              <bitWidth>1</bitWidth>
              <access>read-only</access>
              <enumeratedValues>
                <enumeratedValue>
                  <name>0</name>
                  <description>Module 6 input was not a wakeup source</description>
                  <value>#0</value>
                </enumeratedValue>
                <enumeratedValue>
                  <name>1</name>
                  <description>Module 6 input was a wakeup source</description>
                  <value>#1</value>
                </enumeratedValue>
              </enumeratedValues>
            </field>
            <field>
              <name>MWUF7</name>
              <description>Wakeup flag For module 7</description>
              <bitOffset>7</bitOffset>
              <bitWidth>1</bitWidth>
              <access>read-only</access>
              <enumeratedValues>
                <enumeratedValue>
                  <name>0</name>
                  <description>Module 7 input was not a wakeup source</description>
                  <value>#0</value>
                </enumeratedValue>
                <enumeratedValue>
                  <name>1</name>
                  <description>Module 7 input was a wakeup source</description>
                  <value>#1</value>
                </enumeratedValue>
              </enumeratedValues>
            </field>
          </fields>
        </register>
        <register>
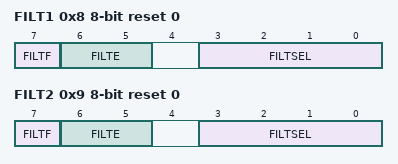
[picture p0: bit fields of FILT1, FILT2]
          <name>FILT1</name>
          <description>LLWU Pin Filter 1 register</description>
          <addressOffset>0x8</addressOffset>
          <size>8</size>
          <access>read-write</access>
          <resetValue>0</resetValue>
          <resetMask>0xFF</resetMask>
          <fields>
            <field>
              <name>FILTSEL</name>
              <description>Filter Pin Select</description>
              <bitOffset>0</bitOffset>
              <bitWidth>4</bitWidth>
              <access>read-write</access>
              <enumeratedValues>
                <enumeratedValue>
                  <name>0000</name>
                  <description>Select LLWU_P0 for filter</description>
                  <value>#0000</value>
                </enumeratedValue>
                <enumeratedValue>
                  <name>1111</name>
                  <description>Select LLWU_P15 for filter</description>
                  <value>#1111</value>
                </enumeratedValue>
              </enumeratedValues>
            </field>
            <field>
              <name>FILTE</name>
              <description>Digital Filter On External Pin</description>
              <bitOffset>5</bitOffset>
              <bitWidth>2</bitWidth>
              <access>read-write</access>
              <enumeratedValues>
                <enumeratedValue>
                  <name>00</name>
                  <description>Filter disabled</description>
                  <value>#00</value>
                </enumeratedValue>
                <enumeratedValue>
                  <name>01</name>
                  <description>Filter posedge detect enabled</description>
                  <value>#01</value>
                </enumeratedValue>
                <enumeratedValue>
                  <name>10</name>
                  <description>Filter negedge detect enabled</description>
                  <value>#10</value>
                </enumeratedValue>
                <enumeratedValue>
                  <name>11</name>
                  <description>Filter any edge detect enabled</description>
                  <value>#11</value>
                </enumeratedValue>
              </enumeratedValues>
            </field>
            <field>
              <name>FILTF</name>
              <description>Filter Detect Flag</description>
              <bitOffset>7</bitOffset>
              <bitWidth>1</bitWidth>
              <access>read-write</access>
              <enumeratedValues>
                <enumeratedValue>
                  <name>0</name>
                  <description>Pin Filter 1 was not a wakeup source</description>
                  <value>#0</value>
                </enumeratedValue>
                <enumeratedValue>
                  <name>1</name>
                  <description>Pin Filter 1 was a wakeup source</description>
                  <value>#1</value>
                </enumeratedValue>
              </enumeratedValues>
            </field>
          </fields>
        </register>
        <register>
          <name>FILT2</name>
          <description>LLWU Pin Filter 2 register</description>
          <addressOffset>0x9</addressOffset>
          <size>8</size>
          <access>read-write</access>
          <resetValue>0</resetValue>
          <resetMask>0xFF</resetMask>
          <fields>
            <field>
              <name>FILTSEL</name>
              <description>Filter Pin Select</description>
              <bitOffset>0</bitOffset>
              <bitWidth>4</bitWidth>
              <access>read-write</access>
              <enumeratedValues>
                <enumeratedValue>
                  <name>0000</name>
                  <description>Select LLWU_P0 for filter</description>
                  <value>#0000</value>
                </enumeratedValue>
                <enumeratedValue>
                  <name>1111</name>
                  <description>Select LLWU_P15 for filter</description>
                  <value>#1111</value>
                </enumeratedValue>
              </enumeratedValues>
            </field>
            <field>
              <name>FILTE</name>
              <description>Digital Filter On External Pin</description>
              <bitOffset>5</bitOffset>
              <bitWidth>2</bitWidth>
              <access>read-write</access>
              <enumeratedValues>
                <enumeratedValue>
                  <name>00</name>
                  <description>Filter disabled</description>
                  <value>#00</value>
                </enumeratedValue>
                <enumeratedValue>
                  <name>01</name>
                  <description>Filter posedge detect enabled</description>
                  <value>#01</value>
                </enumeratedValue>
                <enumeratedValue>
                  <name>10</name>
                  <description>Filter negedge detect enabled</description>
                  <value>#10</value>
                </enumeratedValue>
                <enumeratedValue>
                  <name>11</name>
                  <description>Filter any edge detect enabled</description>
                  <value>#11</value>
                </enumeratedValue>
              </enumeratedValues>
            </field>
            <field>
              <name>FILTF</name>
              <description>Filter Detect Flag</description>
              <bitOffset>7</bitOffset>
              <bitWidth>1</bitWidth>
              <access>read-write</access>
              <enumeratedValues>
                <enumeratedValue>
                  <name>0</name>
                  <description>Pin Filter 2 was not a wakeup source</description>
                  <value>#0</value>
                </enumeratedValue>
                <enumeratedValue>
                  <name>1</name>
                  <description>Pin Filter 2 was a wakeup source</description>
                  <value>#1</value>
                </enumeratedValue>
              </enumeratedValues>
            </field>
          </fields>
        </register>
      </registers>
    </peripheral>
    <peripheral>
      <name>PMC</name>
      <description>Power Management Controller</description>
      <prependToName>PMC_</prependToName>
      <baseAddress>0x4007D000</baseAddress>
      <addressBlock>
        <offset>0</offset>
        <size>0x3</size>
        <usage>registers</usage>
      </addressBlock>
      <interrupt>
        <name>LVD_LVW</name>
        <value>6</value>
      </interrupt>
      <registers>
        <register>
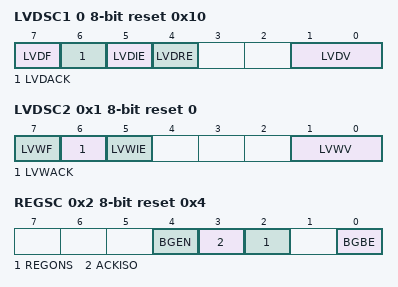
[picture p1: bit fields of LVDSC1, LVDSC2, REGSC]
          <name>LVDSC1</name>
          <description>Low Voltage Detect Status And Control 1 register</description>
          <addressOffset>0</addressOffset>
          <size>8</size>
          <access>read-write</access>
          <resetValue>0x10</resetValue>
          <resetMask>0xFF</resetMask>
          <fields>
            <field>
              <name>LVDV</name>
              <description>Low-Voltage Detect Voltage Select</description>
              <bitOffset>0</bitOffset>
              <bitWidth>2</bitWidth>
              <access>read-write</access>
              <enumeratedValues>
                <enumeratedValue>
                  <name>00</name>
                  <description>Low trip point selected (V LVD = V LVDL )</description>
                  <value>#00</value>
                </enumeratedValue>
                <enumeratedValue>
                  <name>01</name>
                  <description>High trip point selected (V LVD = V LVDH )</description>
                  <value>#01</value>
                </enumeratedValue>
              </enumeratedValues>
            </field>
            <field>
              <name>LVDRE</name>
              <description>Low-Voltage Detect Reset Enable</description>
              <bitOffset>4</bitOffset>
              <bitWidth>1</bitWidth>
              <access>read-write</access>
              <enumeratedValues>
                <enumeratedValue>
                  <name>0</name>
                  <description>LVDF does not generate hardware resets</description>
                  <value>#0</value>
                </enumeratedValue>
                <enumeratedValue>
                  <name>1</name>
                  <description>Force an MCU reset when LVDF = 1</description>
                  <value>#1</value>
                </enumeratedValue>
              </enumeratedValues>
            </field>
            <field>
              <name>LVDIE</name>
              <description>Low-Voltage Detect Interrupt Enable</description>
              <bitOffset>5</bitOffset>
              <bitWidth>1</bitWidth>
              <access>read-write</access>
              <enumeratedValues>
                <enumeratedValue>
                  <name>0</name>
                  <description>Hardware interrupt disabled (use polling)</description>
                  <value>#0</value>
                </enumeratedValue>
                <enumeratedValue>
                  <name>1</name>
                  <description>Request a hardware interrupt when LVDF = 1</description>
                  <value>#1</value>
                </enumeratedValue>
              </enumeratedValues>
            </field>
            <field>
              <name>LVDACK</name>
              <description>Low-Voltage Detect Acknowledge</description>
              <bitOffset>6</bitOffset>
              <bitWidth>1</bitWidth>
              <access>write-only</access>
            </field>
            <field>
              <name>LVDF</name>
              <description>Low-Voltage Detect Flag</description>
              <bitOffset>7</bitOffset>
              <bitWidth>1</bitWidth>
              <access>read-only</access>
              <enumeratedValues>
                <enumeratedValue>
                  <name>0</name>
                  <description>Low-voltage event not detected</description>
                  <value>#0</value>
                </enumeratedValue>
                <enumeratedValue>
                  <name>1</name>
                  <description>Low-voltage event detected</description>
                  <value>#1</value>
                </enumeratedValue>
              </enumeratedValues>
            </field>
          </fields>
        </register>
        <register>
          <name>LVDSC2</name>
          <description>Low Voltage Detect Status And Control 2 register</description>
          <addressOffset>0x1</addressOffset>
          <size>8</size>
          <access>read-write</access>
          <resetValue>0</resetValue>
          <resetMask>0xFF</resetMask>
          <fields>
            <field>
              <name>LVWV</name>
              <description>Low-Voltage Warning Voltage Select</description>
              <bitOffset>0</bitOffset>
              <bitWidth>2</bitWidth>
              <access>read-write</access>
              <enumeratedValues>
                <enumeratedValue>
                  <name>00</name>
                  <description>Low trip point selected (VLVW = VLVW1)</description>
                  <value>#00</value>
                </enumeratedValue>
                <enumeratedValue>
                  <name>01</name>
                  <description>Mid 1 trip point selected (VLVW = VLVW2)</description>
                  <value>#01</value>
                </enumeratedValue>
                <enumeratedValue>
                  <name>10</name>
                  <description>Mid 2 trip point selected (VLVW = VLVW3)</description>
                  <value>#10</value>
                </enumeratedValue>
                <enumeratedValue>
                  <name>11</name>
                  <description>High trip point selected (VLVW = VLVW4)</description>
                  <value>#11</value>
                </enumeratedValue>
              </enumeratedValues>
            </field>
            <field>
              <name>LVWIE</name>
              <description>Low-Voltage Warning Interrupt Enable</description>
              <bitOffset>5</bitOffset>
              <bitWidth>1</bitWidth>
              <access>read-write</access>
              <enumeratedValues>
                <enumeratedValue>
                  <name>0</name>
                  <description>Hardware interrupt disabled (use polling)</description>
                  <value>#0</value>
                </enumeratedValue>
                <enumeratedValue>
                  <name>1</name>
                  <description>Request a hardware interrupt when LVWF = 1</description>
                  <value>#1</value>
                </enumeratedValue>
              </enumeratedValues>
            </field>
            <field>
              <name>LVWACK</name>
              <description>Low-Voltage Warning Acknowledge</description>
              <bitOffset>6</bitOffset>
              <bitWidth>1</bitWidth>
              <access>write-only</access>
            </field>
            <field>
              <name>LVWF</name>
              <description>Low-Voltage Warning Flag</description>
              <bitOffset>7</bitOffset>
              <bitWidth>1</bitWidth>
              <access>read-only</access>
              <enumeratedValues>
                <enumeratedValue>
                  <name>0</name>
                  <description>Low-voltage warning event not detected</description>
                  <value>#0</value>
                </enumeratedValue>
                <enumeratedValue>
                  <name>1</name>
                  <description>Low-voltage warning event detected</description>
                  <value>#1</value>
                </enumeratedValue>
              </enumeratedValues>
            </field>
          </fields>
        </register>
        <register>
          <name>REGSC</name>
          <description>Regulator Status And Control register</description>
          <addressOffset>0x2</addressOffset>
          <size>8</size>
          <access>read-write</access>
          <resetValue>0x4</resetValue>
          <resetMask>0xFF</resetMask>
          <fields>
            <field>
              <name>BGBE</name>
              <description>Bandgap Buffer Enable</description>
              <bitOffset>0</bitOffset>
              <bitWidth>1</bitWidth>
              <access>read-write</access>
              <enumeratedValues>
                <enumeratedValue>
                  <name>0</name>
                  <description>Bandgap buffer not enabled</description>
                  <value>#0</value>
                </enumeratedValue>
                <enumeratedValue>
                  <name>1</name>
                  <description>Bandgap buffer enabled</description>
                  <value>#1</value>
                </enumeratedValue>
              </enumeratedValues>
            </field>
            <field>
              <name>REGONS</name>
              <description>Regulator In Run Regulation Status</description>
              <bitOffset>2</bitOffset>
              <bitWidth>1</bitWidth>
              <access>read-only</access>
              <enumeratedValues>
                <enumeratedValue>
                  <name>0</name>
                  <description>Regulator is in stop regulation or in transition to/from it</description>
                  <value>#0</value>
                </enumeratedValue>
                <enumeratedValue>
                  <name>1</name>
                  <description>Regulator is in run regulation</description>
                  <value>#1</value>
                </enumeratedValue>
              </enumeratedValues>
            </field>
            <field>
              <name>ACKISO</name>
              <description>Acknowledge Isolation</description>
              <bitOffset>3</bitOffset>
              <bitWidth>1</bitWidth>
              <access>read-write</access>
              <enumeratedValues>
                <enumeratedValue>
                  <name>0</name>
                  <description>Peripherals and I/O pads are in normal run state.</description>
                  <value>#0</value>
                </enumeratedValue>
                <enumeratedValue>
                  <name>1</name>
                  <description>Certain peripherals and I/O pads are in an isolated and latched state.</description>
                  <value>#1</value>
                </enumeratedValue>
              </enumeratedValues>
            </field>
            <field>
              <name>BGEN</name>
              <description>Bandgap Enable In VLPx Operation</description>
              <bitOffset>4</bitOffset>
              <bitWidth>1</bitWidth>
              <access>read-write</access>
              <enumeratedValues>
                <enumeratedValue>
                  <name>0</name>
                  <description>Bandgap voltage reference is disabled in VLPx , LLS , and VLLSx modes.</description>
                  <value>#0</value>
                </enumeratedValue>
                <enumeratedValue>
                  <name>1</name>
                  <description>Bandgap voltage reference is enabled in VLPx , LLS , and VLLSx modes.</description>
                  <value>#1</value>
                </enumeratedValue>
              </enumeratedValues>
            </field>
          </fields>
        </register>
      </registers>
    </peripheral>
    <peripheral>
      <name>SMC</name>
      <description>System Mode Controller</description>
      <prependToName>SMC_</prependToName>
      <baseAddress>0x4007E000</baseAddress>
      <addressBlock>
        <offset>0</offset>
        <size>0x4</size>
        <usage>registers</usage>
      </addressBlock>
      <registers>
        <register>
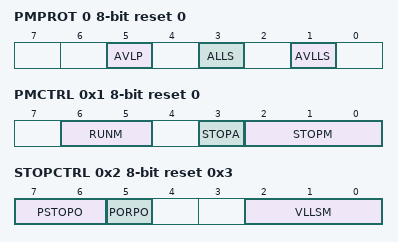
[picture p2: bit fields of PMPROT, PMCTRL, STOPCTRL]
          <name>PMPROT</name>
          <description>Power Mode Protection register</description>
          <addressOffset>0</addressOffset>
          <size>8</size>
          <access>read-write</access>
          <resetValue>0</resetValue>
          <resetMask>0xFF</resetMask>
          <fields>
            <field>
              <name>AVLLS</name>
              <description>Allow Very-Low-Leakage Stop Mode</description>
              <bitOffset>1</bitOffset>
              <bitWidth>1</bitWidth>
              <access>read-write</access>
              <enumeratedValues>
                <enumeratedValue>
                  <name>0</name>
                  <description>Any VLLSx mode is not allowed</description>
                  <value>#0</value>
                </enumeratedValue>
                <enumeratedValue>
                  <name>1</name>
                  <description>Any VLLSx mode is allowed</description>
                  <value>#1</value>
                </enumeratedValue>
              </enumeratedValues>
            </field>
            <field>
              <name>ALLS</name>
              <description>Allow Low-Leakage Stop Mode</description>
              <bitOffset>3</bitOffset>
              <bitWidth>1</bitWidth>
              <access>read-write</access>
              <enumeratedValues>
                <enumeratedValue>
                  <name>0</name>
                  <description>LLS is not allowed</description>
                  <value>#0</value>
                </enumeratedValue>
                <enumeratedValue>
                  <name>1</name>
                  <description>LLS is allowed</description>
                  <value>#1</value>
                </enumeratedValue>
              </enumeratedValues>
            </field>
            <field>
              <name>AVLP</name>
              <description>Allow Very-Low-Power Modes</description>
              <bitOffset>5</bitOffset>
              <bitWidth>1</bitWidth>
              <access>read-write</access>
              <enumeratedValues>
                <enumeratedValue>
                  <name>0</name>
                  <description>VLPR, VLPW, and VLPS are not allowed.</description>
                  <value>#0</value>
                </enumeratedValue>
                <enumeratedValue>
                  <name>1</name>
                  <description>VLPR, VLPW, and VLPS are allowed.</description>
                  <value>#1</value>
                </enumeratedValue>
              </enumeratedValues>
            </field>
          </fields>
        </register>
        <register>
          <name>PMCTRL</name>
          <description>Power Mode Control register</description>
          <addressOffset>0x1</addressOffset>
          <size>8</size>
          <access>read-write</access>
          <resetValue>0</resetValue>
          <resetMask>0xFF</resetMask>
          <fields>
            <field>
              <name>STOPM</name>
              <description>Stop Mode Control</description>
              <bitOffset>0</bitOffset>
              <bitWidth>3</bitWidth>
              <access>read-write</access>
              <enumeratedValues>
                <enumeratedValue>
                  <name>000</name>
                  <description>Normal Stop (STOP)</description>
                  <value>#000</value>
                </enumeratedValue>
                <enumeratedValue>
                  <name>010</name>
                  <description>Very-Low-Power Stop (VLPS)</description>
                  <value>#010</value>
                </enumeratedValue>
                <enumeratedValue>
                  <name>011</name>
                  <description>Low-Leakage Stop (LLS)</description>
                  <value>#011</value>
                </enumeratedValue>
                <enumeratedValue>
                  <name>100</name>
                  <description>Very-Low-Leakage Stop (VLLSx)</description>
                  <value>#100</value>
                </enumeratedValue>
                <enumeratedValue>
                  <name>110</name>
                  <description>Reseved</description>
                  <value>#110</value>
                </enumeratedValue>
              </enumeratedValues>
            </field>
            <field>
              <name>STOPA</name>
              <description>Stop Aborted</description>
              <bitOffset>3</bitOffset>
              <bitWidth>1</bitWidth>
              <access>read-only</access>
              <enumeratedValues>
                <enumeratedValue>
                  <name>0</name>
                  <description>The previous stop mode entry was successsful.</description>
                  <value>#0</value>
                </enumeratedValue>
                <enumeratedValue>
                  <name>1</name>
                  <description>The previous stop mode entry was aborted.</description>
                  <value>#1</value>
                </enumeratedValue>
              </enumeratedValues>
            </field>
            <field>
              <name>RUNM</name>
              <description>Run Mode Control</description>
              <bitOffset>5</bitOffset>
              <bitWidth>2</bitWidth>
              <access>read-write</access>
              <enumeratedValues>
                <enumeratedValue>
                  <name>00</name>
                  <description>Normal Run mode (RUN)</description>
                  <value>#00</value>
                </enumeratedValue>
                <enumeratedValue>
                  <name>10</name>
                  <description>Very-Low-Power Run mode (VLPR)</description>
                  <value>#10</value>
                </enumeratedValue>
              </enumeratedValues>
            </field>
          </fields>
        </register>
        <register>
          <name>STOPCTRL</name>
          <description>Stop Control Register</description>
          <addressOffset>0x2</addressOffset>
          <size>8</size>
          <access>read-write</access>
          <resetValue>0x3</resetValue>
          <resetMask>0xFF</resetMask>
          <fields>
            <field>
              <name>VLLSM</name>
              <description>VLLS Mode Control</description>
              <bitOffset>0</bitOffset>
              <bitWidth>3</bitWidth>
              <access>read-write</access>
              <enumeratedValues>
                <enumeratedValue>
                  <name>000</name>
                  <description>VLLS0</description>
                  <value>#000</value>
                </enumeratedValue>
                <enumeratedValue>
                  <name>001</name>
                  <description>VLLS1</description>
                  <value>#001</value>
                </enumeratedValue>
                <enumeratedValue>
                  <name>011</name>
                  <description>VLLS3</description>
                  <value>#011</value>
                </enumeratedValue>
              </enumeratedValues>
            </field>
            <field>
              <name>PORPO</name>
              <description>POR Power Option</description>
              <bitOffset>5</bitOffset>
              <bitWidth>1</bitWidth>
              <access>read-write</access>
              <enumeratedValues>
                <enumeratedValue>
                  <name>0</name>
                  <description>POR detect circuit is enabled in VLLS0</description>
                  <value>#0</value>
                </enumeratedValue>
                <enumeratedValue>
                  <name>1</name>
                  <description>POR detect circuit is disabled in VLLS0</description>
                  <value>#1</value>
                </enumeratedValue>
              </enumeratedValues>
            </field>
            <field>
              <name>PSTOPO</name>
              <description>Partial Stop Option</description>
              <bitOffset>6</bitOffset>
              <bitWidth>2</bitWidth>
              <access>read-write</access>
              <enumeratedValues>
                <enumeratedValue>
                  <name>00</name>
                  <description>STOP - Normal Stop mode</description>
                  <value>#00</value>
                </enumeratedValue>
                <enumeratedValue>
                  <name>01</name>
                  <description>PSTOP1 - Partial Stop with both system and bus clocks disabled</description>
                  <value>#01</value>
                </enumeratedValue>
                <enumeratedValue>
                  <name>10</name>
                  <description>PSTOP2 - Partial Stop with system clock disabled and bus clock enabled</description>
                  <value>#10</value>
                </enumeratedValue>
              </enumeratedValues>
            </field>
          </fields>
        </register>
        <register>
          <name>PMSTAT</name>
          <description>Power Mode Status register</description>
          <addressOffset>0x3</addressOffset>
          <size>8</size>
          <access>read-only</access>
          <resetValue>0x1</resetValue>
          <resetMask>0xFF</resetMask>
          <fields>
            <field>
              <name>PMSTAT</name>
              <description>When debug is enabled, the PMSTAT will not update to STOP or VLPS When a PSTOP mode is enabled, the PMSTAT will not update to STOP or VLPS</description>
              <bitOffset>0</bitOffset>
              <bitWidth>7</bitWidth>
              <access>read-only</access>
            </field>
          </fields>
        </register>
      </registers>
    </peripheral>
    <peripheral>
      <name>RCM</name>
      <description>Reset Control Module</description>
      <prependToName>RCM_</prependToName>
      <baseAddress>0x4007F000</baseAddress>
      <addressBlock>
        <offset>0</offset>
        <size>0x6</size>
        <usage>registers</usage>
      </addressBlock>
      <registers>
        <register>
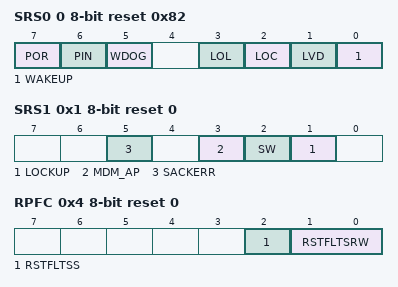
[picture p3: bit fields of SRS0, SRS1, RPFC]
          <name>SRS0</name>
          <description>System Reset Status Register 0</description>
          <addressOffset>0</addressOffset>
          <size>8</size>
          <access>read-only</access>
          <resetValue>0x82</resetValue>
          <resetMask>0xFF</resetMask>
          <fields>
            <field>
              <name>WAKEUP</name>
              <description>Low Leakage Wakeup Reset</description>
              <bitOffset>0</bitOffset>
              <bitWidth>1</bitWidth>
              <access>read-only</access>
              <enumeratedValues>
                <enumeratedValue>
                  <name>0</name>
                  <description>Reset not caused by LLWU module wakeup source</description>
                  <value>#0</value>
                </enumeratedValue>
                <enumeratedValue>
                  <name>1</name>
                  <description>Reset caused by LLWU module wakeup source</description>
                  <value>#1</value>
                </enumeratedValue>
              </enumeratedValues>
            </field>
            <field>
              <name>LVD</name>
              <description>Low-Voltage Detect Reset</description>
              <bitOffset>1</bitOffset>
              <bitWidth>1</bitWidth>
              <access>read-only</access>
              <enumeratedValues>
                <enumeratedValue>
                  <name>0</name>
                  <description>Reset not caused by LVD trip or POR</description>
                  <value>#0</value>
                </enumeratedValue>
                <enumeratedValue>
                  <name>1</name>
                  <description>Reset caused by LVD trip or POR</description>
                  <value>#1</value>
                </enumeratedValue>
              </enumeratedValues>
            </field>
            <field>
              <name>LOC</name>
              <description>Loss-of-Clock Reset</description>
              <bitOffset>2</bitOffset>
              <bitWidth>1</bitWidth>
              <access>read-only</access>
              <enumeratedValues>
                <enumeratedValue>
                  <name>0</name>
                  <description>Reset not caused by a loss of external clock.</description>
                  <value>#0</value>
                </enumeratedValue>
                <enumeratedValue>
                  <name>1</name>
                  <description>Reset caused by a loss of external clock.</description>
                  <value>#1</value>
                </enumeratedValue>
              </enumeratedValues>
            </field>
            <field>
              <name>LOL</name>
              <description>Loss-of-Lock Reset</description>
              <bitOffset>3</bitOffset>
              <bitWidth>1</bitWidth>
              <access>read-only</access>
              <enumeratedValues>
                <enumeratedValue>
                  <name>0</name>
                  <description>Reset not caused by a loss of lock in the PLL</description>
                  <value>#0</value>
                </enumeratedValue>
                <enumeratedValue>
                  <name>1</name>
                  <description>Reset caused by a loss of lock in the PLL</description>
                  <value>#1</value>
                </enumeratedValue>
              </enumeratedValues>
            </field>
            <field>
              <name>WDOG</name>
              <description>Watchdog</description>
              <bitOffset>5</bitOffset>
              <bitWidth>1</bitWidth>
              <access>read-only</access>
              <enumeratedValues>
                <enumeratedValue>
                  <name>0</name>
                  <description>Reset not caused by watchdog timeout</description>
                  <value>#0</value>
                </enumeratedValue>
                <enumeratedValue>
                  <name>1</name>
                  <description>Reset caused by watchdog timeout</description>
                  <value>#1</value>
                </enumeratedValue>
              </enumeratedValues>
            </field>
            <field>
              <name>PIN</name>
              <description>External Reset Pin</description>
              <bitOffset>6</bitOffset>
              <bitWidth>1</bitWidth>
              <access>read-only</access>
              <enumeratedValues>
                <enumeratedValue>
                  <name>0</name>
                  <description>Reset not caused by external reset pin</description>
                  <value>#0</value>
                </enumeratedValue>
                <enumeratedValue>
                  <name>1</name>
                  <description>Reset caused by external reset pin</description>
                  <value>#1</value>
                </enumeratedValue>
              </enumeratedValues>
            </field>
            <field>
              <name>POR</name>
              <description>Power-On Reset</description>
              <bitOffset>7</bitOffset>
              <bitWidth>1</bitWidth>
              <access>read-only</access>
              <enumeratedValues>
                <enumeratedValue>
                  <name>0</name>
                  <description>Reset not caused by POR</description>
                  <value>#0</value>
                </enumeratedValue>
                <enumeratedValue>
                  <name>1</name>
                  <description>Reset caused by POR</description>
                  <value>#1</value>
                </enumeratedValue>
              </enumeratedValues>
            </field>
          </fields>
        </register>
        <register>
          <name>SRS1</name>
          <description>System Reset Status Register 1</description>
          <addressOffset>0x1</addressOffset>
          <size>8</size>
          <access>read-only</access>
          <resetValue>0</resetValue>
          <resetMask>0xFF</resetMask>
          <fields>
            <field>
              <name>LOCKUP</name>
              <description>Core Lockup</description>
              <bitOffset>1</bitOffset>
              <bitWidth>1</bitWidth>
              <access>read-only</access>
              <enumeratedValues>
                <enumeratedValue>
                  <name>0</name>
                  <description>Reset not caused by core LOCKUP event</description>
                  <value>#0</value>
                </enumeratedValue>
                <enumeratedValue>
                  <name>1</name>
                  <description>Reset caused by core LOCKUP event</description>
                  <value>#1</value>
                </enumeratedValue>
              </enumeratedValues>
            </field>
            <field>
              <name>SW</name>
              <description>Software</description>
              <bitOffset>2</bitOffset>
              <bitWidth>1</bitWidth>
              <access>read-only</access>
              <enumeratedValues>
                <enumeratedValue>
                  <name>0</name>
                  <description>Reset not caused by software setting of SYSRESETREQ bit</description>
                  <value>#0</value>
                </enumeratedValue>
                <enumeratedValue>
                  <name>1</name>
                  <description>Reset caused by software setting of SYSRESETREQ bit</description>
                  <value>#1</value>
                </enumeratedValue>
              </enumeratedValues>
            </field>
            <field>
              <name>MDM_AP</name>
              <description>MDM-AP System Reset Request</description>
              <bitOffset>3</bitOffset>
              <bitWidth>1</bitWidth>
              <access>read-only</access>
              <enumeratedValues>
                <enumeratedValue>
                  <name>0</name>
                  <description>Reset not caused by host debugger system setting of the System Reset Request bit</description>
                  <value>#0</value>
                </enumeratedValue>
                <enumeratedValue>
                  <name>1</name>
                  <description>Reset caused by host debugger system setting of the System Reset Request bit</description>
                  <value>#1</value>
                </enumeratedValue>
              </enumeratedValues>
            </field>
            <field>
              <name>SACKERR</name>
              <description>Stop Mode Acknowledge Error Reset</description>
              <bitOffset>5</bitOffset>
              <bitWidth>1</bitWidth>
              <access>read-only</access>
              <enumeratedValues>
                <enumeratedValue>
                  <name>0</name>
                  <description>Reset not caused by peripheral failure to acknowledge attempt to enter stop mode</description>
                  <value>#0</value>
                </enumeratedValue>
                <enumeratedValue>
                  <name>1</name>
                  <description>Reset caused by peripheral failure to acknowledge attempt to enter stop mode</description>
                  <value>#1</value>
                </enumeratedValue>
              </enumeratedValues>
            </field>
          </fields>
        </register>
        <register>
          <name>RPFC</name>
          <description>Reset Pin Filter Control register</description>
          <addressOffset>0x4</addressOffset>
          <size>8</size>
          <access>read-write</access>
          <resetValue>0</resetValue>
          <resetMask>0xFF</resetMask>
          <fields>
            <field>
              <name>RSTFLTSRW</name>
              <description>Reset Pin Filter Select in Run and Wait Modes</description>
              <bitOffset>0</bitOffset>
              <bitWidth>2</bitWidth>
              <access>read-write</access>
              <enumeratedValues>
                <enumeratedValue>
                  <name>00</name>
                  <description>All filtering disabled</description>
                  <value>#00</value>
                </enumeratedValue>
                <enumeratedValue>
                  <name>01</name>
                  <description>Bus clock filter enabled for normal operation</description>
                  <value>#01</value>
                </enumeratedValue>
                <enumeratedValue>
                  <name>10</name>
                  <description>LPO clock filter enabled for normal operation</description>
                  <value>#10</value>
                </enumeratedValue>
              </enumeratedValues>
            </field>
            <field>
              <name>RSTFLTSS</name>
              <description>Reset Pin Filter Select in Stop Mode</description>
              <bitOffset>2</bitOffset>
              <bitWidth>1</bitWidth>
              <access>read-write</access>
              <enumeratedValues>
                <enumeratedValue>
                  <name>0</name>
                  <description>All filtering disabled</description>
                  <value>#0</value>
                </enumeratedValue>
                <enumeratedValue>
                  <name>1</name>
                  <description>LPO clock filter enabled</description>
                  <value>#1</value>
                </enumeratedValue>
              </enumeratedValues>
            </field>
          </fields>
        </register>
        <register>
          <name>RPFW</name>
          <description>Reset Pin Filter Width register</description>
          <addressOffset>0x5</addressOffset>
          <size>8</size>
          <access>read-write</access>
          <resetValue>0</resetValue>
          <resetMask>0xFF</resetMask>
          <fields>
            <field>
              <name>RSTFLTSEL</name>
              <description>Reset Pin Filter Bus Clock Select</description>
              <bitOffset>0</bitOffset>
              <bitWidth>5</bitWidth>
              <access>read-write</access>
              <enumeratedValues>
                <enumeratedValue>
                  <name>00000</name>
                  <description>Bus clock filter count is 1</description>
                  <value>#00000</value>
                </enumeratedValue>
                <enumeratedValue>
                  <name>00001</name>
                  <description>Bus clock filter count is 2</description>
                  <value>#00001</value>
                </enumeratedValue>
                <enumeratedValue>
                  <name>00010</name>
                  <description>Bus clock filter count is 3</description>
                  <value>#00010</value>
                </enumeratedValue>
                <enumeratedValue>
                  <name>00011</name>
                  <description>Bus clock filter count is 4</description>
                  <value>#00011</value>
                </enumeratedValue>
                <enumeratedValue>
                  <name>00100</name>
                  <description>Bus clock filter count is 5</description>
                  <value>#00100</value>
                </enumeratedValue>
                <enumeratedValue>
                  <name>00101</name>
                  <description>Bus clock filter count is 6</description>
                  <value>#00101</value>
                </enumeratedValue>
                <enumeratedValue>
                  <name>00110</name>
                  <description>Bus clock filter count is 7</description>
                  <value>#00110</value>
                </enumeratedValue>
                <enumeratedValue>
                  <name>00111</name>
                  <description>Bus clock filter count is 8</description>
                  <value>#00111</value>
                </enumeratedValue>
                <enumeratedValue>
                  <name>01000</name>
                  <description>Bus clock filter count is 9</description>
                  <value>#01000</value>
                </enumeratedValue>
                <enumeratedValue>
                  <name>01001</name>
                  <description>Bus clock filter count is 10</description>
                  <value>#01001</value>
                </enumeratedValue>
                <enumeratedValue>
                  <name>01010</name>
                  <description>Bus clock filter count is 11</description>
                  <value>#01010</value>
                </enumeratedValue>
                <enumeratedValue>
                  <name>01011</name>
                  <description>Bus clock filter count is 12</description>
                  <value>#01011</value>
                </enumeratedValue>
                <enumeratedValue>
                  <name>01100</name>
                  <description>Bus clock filter count is 13</description>
                  <value>#01100</value>
                </enumeratedValue>
                <enumeratedValue>
                  <name>01101</name>
                  <description>Bus clock filter count is 14</description>
                  <value>#01101</value>
                </enumeratedValue>
                <enumeratedValue>
                  <name>01110</name>
                  <description>Bus clock filter count is 15</description>
                  <value>#01110</value>
                </enumeratedValue>
                <enumeratedValue>
                  <name>01111</name>
                  <description>Bus clock filter count is 16</description>
                  <value>#01111</value>
                </enumeratedValue>
                <enumeratedValue>
                  <name>10000</name>
                  <description>Bus clock filter count is 17</description>
                  <value>#10000</value>
                </enumeratedValue>
                <enumeratedValue>
                  <name>10001</name>
                  <description>Bus clock filter count is 18</description>
                  <value>#10001</value>
                </enumeratedValue>
                <enumeratedValue>
                  <name>10010</name>
                  <description>Bus clock filter count is 19</description>
                  <value>#10010</value>
                </enumeratedValue>
                <enumeratedValue>
                  <name>10011</name>
                  <description>Bus clock filter count is 20</description>
                  <value>#10011</value>
                </enumeratedValue>
                <enumeratedValue>
                  <name>10100</name>
                  <description>Bus clock filter count is 21</description>
                  <value>#10100</value>
                </enumeratedValue>
                <enumeratedValue>
                  <name>10101</name>
                  <description>Bus clock filter count is 22</description>
                  <value>#10101</value>
                </enumeratedValue>
                <enumeratedValue>
                  <name>10110</name>
                  <description>Bus clock filter count is 23</description>
                  <value>#10110</value>
                </enumeratedValue>
                <enumeratedValue>
                  <name>10111</name>
                  <description>Bus clock filter count is 24</description>
                  <value>#10111</value>
                </enumeratedValue>
                <enumeratedValue>
                  <name>11000</name>
                  <description>Bus clock filter count is 25</description>
                  <value>#11000</value>
                </enumeratedValue>
                <enumeratedValue>
                  <name>11001</name>
                  <description>Bus clock filter count is 26</description>
                  <value>#11001</value>
                </enumeratedValue>
                <enumeratedValue>
                  <name>11010</name>
                  <description>Bus clock filter count is 27</description>
                  <value>#11010</value>
                </enumeratedValue>
                <enumeratedValue>
                  <name>11011</name>
                  <description>Bus clock filter count is 28</description>
                  <value>#11011</value>
                </enumeratedValue>
                <enumeratedValue>
                  <name>11100</name>
                  <description>Bus clock filter count is 29</description>
                  <value>#11100</value>
                </enumeratedValue>
                <enumeratedValue>
                  <name>11101</name>
                  <description>Bus clock filter count is 30</description>
                  <value>#11101</value>
                </enumeratedValue>
                <enumeratedValue>
                  <name>11110</name>
                  <description>Bus clock filter count is 31</description>
                  <value>#11110</value>
                </enumeratedValue>
                <enumeratedValue>
                  <name>11111</name>
                  <description>Bus clock filter count is 32</description>
                  <value>#11111</value>
                </enumeratedValue>
              </enumeratedValues>
            </field>
          </fields>
        </register>
      </registers>
    </peripheral>
    <peripheral>
      <name>GPIOA</name>
      <description>General Purpose Input/Output</description>
      <groupName>GPIO</groupName>
      <prependToName>GPIOA_</prependToName>
      <baseAddress>0x400FF000</baseAddress>
      <addressBlock>
        <offset>0</offset>
        <size>0x18</size>
        <usage>registers</usage>
      </addressBlock>
      <interrupt>
        <name>PORTA</name>
        <value>30</value>
      </interrupt>
      <registers>
        <register>
          <name>PDOR</name>
          <description>Port Data Output Register</description>
          <addressOffset>0</addressOffset>
          <size>32</size>
          <access>read-write</access>
          <resetValue>0</resetValue>
          <resetMask>0xFFFFFFFF</resetMask>
          <fields>
            <field>
              <name>PDO</name>
              <description>Port Data Output</description>
              <bitOffset>0</bitOffset>
              <bitWidth>32</bitWidth>
              <access>read-write</access>
              <enumeratedValues>
                <enumeratedValue>
                  <name>0</name>
                  <description>Logic level 0 is driven on pin, provided pin is configured for general-purpose output.</description>
                  <value>#0</value>
                </enumeratedValue>
                <enumeratedValue>
                  <name>1</name>
                  <description>Logic level 1 is driven on pin, provided pin is configured for general-purpose output.</description>
                  <value>#1</value>
                </enumeratedValue>
              </enumeratedValues>
            </field>
          </fields>
        </register>
        <register>
          <name>PSOR</name>
          <description>Port Set Output Register</description>
          <addressOffset>0x4</addressOffset>
          <size>32</size>
          <access>write-only</access>
          <resetValue>0</resetValue>
          <resetMask>0xFFFFFFFF</resetMask>
          <fields>
            <field>
              <name>PTSO</name>
              <description>Port Set Output</description>
              <bitOffset>0</bitOffset>
              <bitWidth>32</bitWidth>
              <access>write-only</access>
              <enumeratedValues>
                <enumeratedValue>
                  <name>0</name>
                  <description>Corresponding bit in PDORn does not change.</description>
                  <value>#0</value>
                </enumeratedValue>
                <enumeratedValue>
                  <name>1</name>
                  <description>Corresponding bit in PDORn is set to logic 1.</description>
                  <value>#1</value>
                </enumeratedValue>
              </enumeratedValues>
            </field>
          </fields>
        </register>
        <register>
          <name>PCOR</name>
          <description>Port Clear Output Register</description>
          <addressOffset>0x8</addressOffset>
          <size>32</size>
          <access>write-only</access>
          <resetValue>0</resetValue>
          <resetMask>0xFFFFFFFF</resetMask>
          <fields>
            <field>
              <name>PTCO</name>
              <description>Port Clear Output</description>
              <bitOffset>0</bitOffset>
              <bitWidth>32</bitWidth>
              <access>write-only</access>
              <enumeratedValues>
                <enumeratedValue>
                  <name>0</name>
                  <description>Corresponding bit in PDORn does not change.</description>
                  <value>#0</value>
                </enumeratedValue>
                <enumeratedValue>
                  <name>1</name>
                  <description>Corresponding bit in PDORn is cleared to logic 0.</description>
                  <value>#1</value>
                </enumeratedValue>
              </enumeratedValues>
            </field>
          </fields>
        </register>
        <register>
          <name>PTOR</name>
          <description>Port Toggle Output Register</description>
          <addressOffset>0xC</addressOffset>
          <size>32</size>
          <access>write-only</access>
          <resetValue>0</resetValue>
          <resetMask>0xFFFFFFFF</resetMask>
          <fields>
            <field>
              <name>PTTO</name>
              <description>Port Toggle Output</description>
              <bitOffset>0</bitOffset>
              <bitWidth>32</bitWidth>
              <access>write-only</access>
              <enumeratedValues>
                <enumeratedValue>
                  <name>0</name>
                  <description>Corresponding bit in PDORn does not change.</description>
                  <value>#0</value>
                </enumeratedValue>
                <enumeratedValue>
                  <name>1</name>
                  <description>Corresponding bit in PDORn is set to the inverse of its existing logic state.</description>
                  <value>#1</value>
                </enumeratedValue>
              </enumeratedValues>
            </field>
          </fields>
        </register>
        <register>
          <name>PDIR</name>
          <description>Port Data Input Register</description>
          <addressOffset>0x10</addressOffset>
          <size>32</size>
          <access>read-only</access>
          <resetValue>0</resetValue>
          <resetMask>0xFFFFFFFF</resetMask>
          <fields>
            <field>
              <name>PDI</name>
              <description>Port Data Input</description>
              <bitOffset>0</bitOffset>
              <bitWidth>32</bitWidth>
              <access>read-only</access>
              <enumeratedValues>
                <enumeratedValue>
                  <name>0</name>
                  <description>Pin logic level is logic 0, or is not configured for use by digital function.</description>
                  <value>#0</value>
                </enumeratedValue>
                <enumeratedValue>
                  <name>1</name>
                  <description>Pin logic level is logic 1.</description>
                  <value>#1</value>
                </enumeratedValue>
              </enumeratedValues>
            </field>
          </fields>
        </register>
        <register>
          <name>PDDR</name>
          <description>Port Data Direction Register</description>
          <addressOffset>0x14</addressOffset>
          <size>32</size>
          <access>read-write</access>
          <resetValue>0</resetValue>
          <resetMask>0xFFFFFFFF</resetMask>
          <fields>
            <field>
              <name>PDD</name>
              <description>Port Data Direction</description>
              <bitOffset>0</bitOffset>
              <bitWidth>32</bitWidth>
              <access>read-write</access>
              <enumeratedValues>
                <enumeratedValue>
                  <name>0</name>
                  <description>Pin is configured as general-purpose input, for the GPIO function.</description>
                  <value>#0</value>
                </enumeratedValue>
                <enumeratedValue>
                  <name>1</name>
                  <description>Pin is configured as general-purpose output, for the GPIO function.</description>
                  <value>#1</value>
                </enumeratedValue>
              </enumeratedValues>
            </field>
          </fields>
        </register>
      </registers>
    </peripheral>
    <peripheral>
      <name>GPIOB</name>
      <description>General Purpose Input/Output</description>
      <groupName>GPIO</groupName>
      <prependToName>GPIOB_</prependToName>
      <baseAddress>0x400FF040</baseAddress>
      <addressBlock>
        <offset>0</offset>
        <size>0x18</size>
        <usage>registers</usage>
      </addressBlock>
      <registers>
        <register>
          <name>PDOR</name>
          <description>Port Data Output Register</description>
          <addressOffset>0</addressOffset>
          <size>32</size>
          <access>read-write</access>
          <resetValue>0</resetValue>
          <resetMask>0xFFFFFFFF</resetMask>
          <fields>
            <field>
              <name>PDO</name>
              <description>Port Data Output</description>
              <bitOffset>0</bitOffset>
              <bitWidth>32</bitWidth>
              <access>read-write</access>
              <enumeratedValues>
                <enumeratedValue>
                  <name>0</name>
                  <description>Logic level 0 is driven on pin, provided pin is configured for general-purpose output.</description>
                  <value>#0</value>
                </enumeratedValue>
                <enumeratedValue>
                  <name>1</name>
                  <description>Logic level 1 is driven on pin, provided pin is configured for general-purpose output.</description>
                  <value>#1</value>
                </enumeratedValue>
              </enumeratedValues>
            </field>
          </fields>
        </register>
        <register>
          <name>PSOR</name>
          <description>Port Set Output Register</description>
          <addressOffset>0x4</addressOffset>
          <size>32</size>
          <access>write-only</access>
          <resetValue>0</resetValue>
          <resetMask>0xFFFFFFFF</resetMask>
          <fields>
            <field>
              <name>PTSO</name>
              <description>Port Set Output</description>
              <bitOffset>0</bitOffset>
              <bitWidth>32</bitWidth>
              <access>write-only</access>
              <enumeratedValues>
                <enumeratedValue>
                  <name>0</name>
                  <description>Corresponding bit in PDORn does not change.</description>
                  <value>#0</value>
                </enumeratedValue>
                <enumeratedValue>
                  <name>1</name>
                  <description>Corresponding bit in PDORn is set to logic 1.</description>
                  <value>#1</value>
                </enumeratedValue>
              </enumeratedValues>
            </field>
          </fields>
        </register>
        <register>
          <name>PCOR</name>
          <description>Port Clear Output Register</description>
          <addressOffset>0x8</addressOffset>
          <size>32</size>
          <access>write-only</access>
          <resetValue>0</resetValue>
          <resetMask>0xFFFFFFFF</resetMask>
          <fields>
            <field>
              <name>PTCO</name>
              <description>Port Clear Output</description>
              <bitOffset>0</bitOffset>
              <bitWidth>32</bitWidth>
              <access>write-only</access>
              <enumeratedValues>
                <enumeratedValue>
                  <name>0</name>
                  <description>Corresponding bit in PDORn does not change.</description>
                  <value>#0</value>
                </enumeratedValue>
                <enumeratedValue>
                  <name>1</name>
                  <description>Corresponding bit in PDORn is cleared to logic 0.</description>
                  <value>#1</value>
                </enumeratedValue>
              </enumeratedValues>
            </field>
          </fields>
        </register>
        <register>
          <name>PTOR</name>
          <description>Port Toggle Output Register</description>
          <addressOffset>0xC</addressOffset>
          <size>32</size>
          <access>write-only</access>
          <resetValue>0</resetValue>
          <resetMask>0xFFFFFFFF</resetMask>
          <fields>
            <field>
              <name>PTTO</name>
              <description>Port Toggle Output</description>
              <bitOffset>0</bitOffset>
              <bitWidth>32</bitWidth>
              <access>write-only</access>
              <enumeratedValues>
                <enumeratedValue>
                  <name>0</name>
                  <description>Corresponding bit in PDORn does not change.</description>
                  <value>#0</value>
                </enumeratedValue>
                <enumeratedValue>
                  <name>1</name>
                  <description>Corresponding bit in PDORn is set to the inverse of its existing logic state.</description>
                  <value>#1</value>
                </enumeratedValue>
              </enumeratedValues>
            </field>
          </fields>
        </register>
        <register>
          <name>PDIR</name>
          <description>Port Data Input Register</description>
          <addressOffset>0x10</addressOffset>
          <size>32</size>
          <access>read-only</access>
          <resetValue>0</resetValue>
          <resetMask>0xFFFFFFFF</resetMask>
          <fields>
            <field>
              <name>PDI</name>
              <description>Port Data Input</description>
              <bitOffset>0</bitOffset>
              <bitWidth>32</bitWidth>
              <access>read-only</access>
              <enumeratedValues>
                <enumeratedValue>
                  <name>0</name>
                  <description>Pin logic level is logic 0, or is not configured for use by digital function.</description>
                  <value>#0</value>
                </enumeratedValue>
                <enumeratedValue>
                  <name>1</name>
                  <description>Pin logic level is logic 1.</description>
                  <value>#1</value>
                </enumeratedValue>
              </enumeratedValues>
            </field>
          </fields>
        </register>
        <register>
          <name>PDDR</name>
          <description>Port Data Direction Register</description>
          <addressOffset>0x14</addressOffset>
          <size>32</size>
          <access>read-write</access>
          <resetValue>0</resetValue>
          <resetMask>0xFFFFFFFF</resetMask>
          <fields>
            <field>
              <name>PDD</name>
              <description>Port Data Direction</description>
              <bitOffset>0</bitOffset>
              <bitWidth>32</bitWidth>
              <access>read-write</access>
              <enumeratedValues>
                <enumeratedValue>
                  <name>0</name>
                  <description>Pin is configured as general-purpose input, for the GPIO function.</description>
                  <value>#0</value>
                </enumeratedValue>
                <enumeratedValue>
                  <name>1</name>
                  <description>Pin is configured as general-purpose output, for the GPIO function.</description>
                  <value>#1</value>
                </enumeratedValue>
              </enumeratedValues>
            </field>
          </fields>
        </register>
      </registers>
    </peripheral>
    <peripheral>
      <name>GPIOC</name>
      <description>General Purpose Input/Output</description>
      <groupName>GPIO</groupName>
      <prependToName>GPIOC_</prependToName>
      <baseAddress>0x400FF080</baseAddress>
      <addressBlock>
        <offset>0</offset>
        <size>0x18</size>
        <usage>registers</usage>
      </addressBlock>
      <interrupt>
        <name>PORTC_PORTD</name>
        <value>31</value>
      </interrupt>
      <registers>
        <register>
          <name>PDOR</name>
          <description>Port Data Output Register</description>
          <addressOffset>0</addressOffset>
          <size>32</size>
          <access>read-write</access>
          <resetValue>0</resetValue>
          <resetMask>0xFFFFFFFF</resetMask>
          <fields>
            <field>
              <name>PDO</name>
              <description>Port Data Output</description>
              <bitOffset>0</bitOffset>
              <bitWidth>32</bitWidth>
              <access>read-write</access>
              <enumeratedValues>
                <enumeratedValue>
                  <name>0</name>
                  <description>Logic level 0 is driven on pin, provided pin is configured for general-purpose output.</description>
                  <value>#0</value>
                </enumeratedValue>
                <enumeratedValue>
                  <name>1</name>
                  <description>Logic level 1 is driven on pin, provided pin is configured for general-purpose output.</description>
                  <value>#1</value>
                </enumeratedValue>
              </enumeratedValues>
            </field>
          </fields>
        </register>
        <register>
          <name>PSOR</name>
          <description>Port Set Output Register</description>
          <addressOffset>0x4</addressOffset>
          <size>32</size>
          <access>write-only</access>
          <resetValue>0</resetValue>
          <resetMask>0xFFFFFFFF</resetMask>
          <fields>
            <field>
              <name>PTSO</name>
              <description>Port Set Output</description>
              <bitOffset>0</bitOffset>
              <bitWidth>32</bitWidth>
              <access>write-only</access>
              <enumeratedValues>
                <enumeratedValue>
                  <name>0</name>
                  <description>Corresponding bit in PDORn does not change.</description>
                  <value>#0</value>
                </enumeratedValue>
                <enumeratedValue>
                  <name>1</name>
                  <description>Corresponding bit in PDORn is set to logic 1.</description>
                  <value>#1</value>
                </enumeratedValue>
              </enumeratedValues>
            </field>
          </fields>
        </register>
        <register>
          <name>PCOR</name>
          <description>Port Clear Output Register</description>
          <addressOffset>0x8</addressOffset>
          <size>32</size>
          <access>write-only</access>
          <resetValue>0</resetValue>
          <resetMask>0xFFFFFFFF</resetMask>
          <fields>
            <field>
              <name>PTCO</name>
              <description>Port Clear Output</description>
              <bitOffset>0</bitOffset>
              <bitWidth>32</bitWidth>
              <access>write-only</access>
              <enumeratedValues>
                <enumeratedValue>
                  <name>0</name>
                  <description>Corresponding bit in PDORn does not change.</description>
                  <value>#0</value>
                </enumeratedValue>
                <enumeratedValue>
                  <name>1</name>
                  <description>Corresponding bit in PDORn is cleared to logic 0.</description>
                  <value>#1</value>
                </enumeratedValue>
              </enumeratedValues>
            </field>
          </fields>
        </register>
        <register>
          <name>PTOR</name>
          <description>Port Toggle Output Register</description>
          <addressOffset>0xC</addressOffset>
          <size>32</size>
          <access>write-only</access>
          <resetValue>0</resetValue>
          <resetMask>0xFFFFFFFF</resetMask>
          <fields>
            <field>
              <name>PTTO</name>
              <description>Port Toggle Output</description>
              <bitOffset>0</bitOffset>
              <bitWidth>32</bitWidth>
              <access>write-only</access>
              <enumeratedValues>
                <enumeratedValue>
                  <name>0</name>
                  <description>Corresponding bit in PDORn does not change.</description>
                  <value>#0</value>
                </enumeratedValue>
                <enumeratedValue>
                  <name>1</name>
                  <description>Corresponding bit in PDORn is set to the inverse of its existing logic state.</description>
                  <value>#1</value>
                </enumeratedValue>
              </enumeratedValues>
            </field>
          </fields>
        </register>
        <register>
          <name>PDIR</name>
          <description>Port Data Input Register</description>
          <addressOffset>0x10</addressOffset>
          <size>32</size>
          <access>read-only</access>
          <resetValue>0</resetValue>
          <resetMask>0xFFFFFFFF</resetMask>
          <fields>
            <field>
              <name>PDI</name>
              <description>Port Data Input</description>
              <bitOffset>0</bitOffset>
              <bitWidth>32</bitWidth>
              <access>read-only</access>
              <enumeratedValues>
                <enumeratedValue>
                  <name>0</name>
                  <description>Pin logic level is logic 0, or is not configured for use by digital function.</description>
                  <value>#0</value>
                </enumeratedValue>
                <enumeratedValue>
                  <name>1</name>
                  <description>Pin logic level is logic 1.</description>
                  <value>#1</value>
                </enumeratedValue>
              </enumeratedValues>
            </field>
          </fields>
        </register>
        <register>
          <name>PDDR</name>
          <description>Port Data Direction Register</description>
          <addressOffset>0x14</addressOffset>
          <size>32</size>
          <access>read-write</access>
          <resetValue>0</resetValue>
          <resetMask>0xFFFFFFFF</resetMask>
          <fields>
            <field>
              <name>PDD</name>
              <description>Port Data Direction</description>
              <bitOffset>0</bitOffset>
              <bitWidth>32</bitWidth>
              <access>read-write</access>
              <enumeratedValues>
                <enumeratedValue>
                  <name>0</name>
                  <description>Pin is configured as general-purpose input, for the GPIO function.</description>
                  <value>#0</value>
                </enumeratedValue>
                <enumeratedValue>
                  <name>1</name>
                  <description>Pin is configured as general-purpose output, for the GPIO function.</description>
                  <value>#1</value>
                </enumeratedValue>
              </enumeratedValues>
            </field>
          </fields>
        </register>
      </registers>
    </peripheral>
    <peripheral>
      <name>GPIOD</name>
      <description>General Purpose Input/Output</description>
      <groupName>GPIO</groupName>
      <prependToName>GPIOD_</prependToName>
      <baseAddress>0x400FF0C0</baseAddress>
      <addressBlock>
        <offset>0</offset>
        <size>0x18</size>
        <usage>registers</usage>
      </addressBlock>
      <interrupt>
        <name>PORTC_PORTD</name>
        <value>31</value>
      </interrupt>
      <registers>
        <register>
          <name>PDOR</name>
          <description>Port Data Output Register</description>
          <addressOffset>0</addressOffset>
          <size>32</size>
          <access>read-write</access>
          <resetValue>0</resetValue>
          <resetMask>0xFFFFFFFF</resetMask>
          <fields>
            <field>
              <name>PDO</name>
              <description>Port Data Output</description>
              <bitOffset>0</bitOffset>
              <bitWidth>32</bitWidth>
              <access>read-write</access>
              <enumeratedValues>
                <enumeratedValue>
                  <name>0</name>
                  <description>Logic level 0 is driven on pin, provided pin is configured for general-purpose output.</description>
                  <value>#0</value>
                </enumeratedValue>
                <enumeratedValue>
                  <name>1</name>
                  <description>Logic level 1 is driven on pin, provided pin is configured for general-purpose output.</description>
                  <value>#1</value>
                </enumeratedValue>
              </enumeratedValues>
            </field>
          </fields>
        </register>
        <register>
          <name>PSOR</name>
          <description>Port Set Output Register</description>
          <addressOffset>0x4</addressOffset>
          <size>32</size>
          <access>write-only</access>
          <resetValue>0</resetValue>
          <resetMask>0xFFFFFFFF</resetMask>
          <fields>
            <field>
              <name>PTSO</name>
              <description>Port Set Output</description>
              <bitOffset>0</bitOffset>
              <bitWidth>32</bitWidth>
              <access>write-only</access>
              <enumeratedValues>
                <enumeratedValue>
                  <name>0</name>
                  <description>Corresponding bit in PDORn does not change.</description>
                  <value>#0</value>
                </enumeratedValue>
                <enumeratedValue>
                  <name>1</name>
                  <description>Corresponding bit in PDORn is set to logic 1.</description>
                  <value>#1</value>
                </enumeratedValue>
              </enumeratedValues>
            </field>
          </fields>
        </register>
        <register>
          <name>PCOR</name>
          <description>Port Clear Output Register</description>
          <addressOffset>0x8</addressOffset>
          <size>32</size>
          <access>write-only</access>
          <resetValue>0</resetValue>
          <resetMask>0xFFFFFFFF</resetMask>
          <fields>
            <field>
              <name>PTCO</name>
              <description>Port Clear Output</description>
              <bitOffset>0</bitOffset>
              <bitWidth>32</bitWidth>
              <access>write-only</access>
              <enumeratedValues>
                <enumeratedValue>
                  <name>0</name>
                  <description>Corresponding bit in PDORn does not change.</description>
                  <value>#0</value>
                </enumeratedValue>
                <enumeratedValue>
                  <name>1</name>
                  <description>Corresponding bit in PDORn is cleared to logic 0.</description>
                  <value>#1</value>
                </enumeratedValue>
              </enumeratedValues>
            </field>
          </fields>
        </register>
        <register>
          <name>PTOR</name>
          <description>Port Toggle Output Register</description>
          <addressOffset>0xC</addressOffset>
          <size>32</size>
          <access>write-only</access>
          <resetValue>0</resetValue>
          <resetMask>0xFFFFFFFF</resetMask>
          <fields>
            <field>
              <name>PTTO</name>
              <description>Port Toggle Output</description>
              <bitOffset>0</bitOffset>
              <bitWidth>32</bitWidth>
              <access>write-only</access>
              <enumeratedValues>
                <enumeratedValue>
                  <name>0</name>
                  <description>Corresponding bit in PDORn does not change.</description>
                  <value>#0</value>
                </enumeratedValue>
                <enumeratedValue>
                  <name>1</name>
                  <description>Corresponding bit in PDORn is set to the inverse of its existing logic state.</description>
                  <value>#1</value>
                </enumeratedValue>
              </enumeratedValues>
            </field>
          </fields>
        </register>
        <register>
          <name>PDIR</name>
          <description>Port Data Input Register</description>
          <addressOffset>0x10</addressOffset>
          <size>32</size>
          <access>read-only</access>
          <resetValue>0</resetValue>
          <resetMask>0xFFFFFFFF</resetMask>
          <fields>
            <field>
              <name>PDI</name>
              <description>Port Data Input</description>
              <bitOffset>0</bitOffset>
              <bitWidth>32</bitWidth>
              <access>read-only</access>
              <enumeratedValues>
                <enumeratedValue>
                  <name>0</name>
                  <description>Pin logic level is logic 0, or is not configured for use by digital function.</description>
                  <value>#0</value>
                </enumeratedValue>
                <enumeratedValue>
                  <name>1</name>
                  <description>Pin logic level is logic 1.</description>
                  <value>#1</value>
                </enumeratedValue>
              </enumeratedValues>
            </field>
          </fields>
        </register>
        <register>
          <name>PDDR</name>
          <description>Port Data Direction Register</description>
          <addressOffset>0x14</addressOffset>
          <size>32</size>
          <access>read-write</access>
          <resetValue>0</resetValue>
          <resetMask>0xFFFFFFFF</resetMask>
          <fields>
            <field>
              <name>PDD</name>
              <description>Port Data Direction</description>
              <bitOffset>0</bitOffset>
              <bitWidth>32</bitWidth>
              <access>read-write</access>
              <enumeratedValues>
                <enumeratedValue>
                  <name>0</name>
                  <description>Pin is configured as general-purpose input, for the GPIO function.</description>
                  <value>#0</value>
                </enumeratedValue>
                <enumeratedValue>
                  <name>1</name>
                  <description>Pin is configured as general-purpose output, for the GPIO function.</description>
                  <value>#1</value>
                </enumeratedValue>
              </enumeratedValues>
            </field>
          </fields>
        </register>
      </registers>
    </peripheral>
    <peripheral>
      <name>GPIOE</name>
      <description>General Purpose Input/Output</description>
      <groupName>GPIO</groupName>
      <prependToName>GPIOE_</prependToName>
      <baseAddress>0x400FF100</baseAddress>
      <addressBlock>
        <offset>0</offset>
        <size>0x18</size>
        <usage>registers</usage>
      </addressBlock>
      <registers>
        <register>
          <name>PDOR</name>
          <description>Port Data Output Register</description>
          <addressOffset>0</addressOffset>
          <size>32</size>
          <access>read-write</access>
          <resetValue>0</resetValue>
          <resetMask>0xFFFFFFFF</resetMask>
          <fields>
            <field>
              <name>PDO</name>
              <description>Port Data Output</description>
              <bitOffset>0</bitOffset>
              <bitWidth>32</bitWidth>
              <access>read-write</access>
              <enumeratedValues>
                <enumeratedValue>
                  <name>0</name>
                  <description>Logic level 0 is driven on pin, provided pin is configured for general-purpose output.</description>
                  <value>#0</value>
                </enumeratedValue>
                <enumeratedValue>
                  <name>1</name>
                  <description>Logic level 1 is driven on pin, provided pin is configured for general-purpose output.</description>
                  <value>#1</value>
                </enumeratedValue>
              </enumeratedValues>
            </field>
          </fields>
        </register>
        <register>
          <name>PSOR</name>
          <description>Port Set Output Register</description>
          <addressOffset>0x4</addressOffset>
          <size>32</size>
          <access>write-only</access>
          <resetValue>0</resetValue>
          <resetMask>0xFFFFFFFF</resetMask>
          <fields>
            <field>
              <name>PTSO</name>
              <description>Port Set Output</description>
              <bitOffset>0</bitOffset>
              <bitWidth>32</bitWidth>
              <access>write-only</access>
              <enumeratedValues>
                <enumeratedValue>
                  <name>0</name>
                  <description>Corresponding bit in PDORn does not change.</description>
                  <value>#0</value>
                </enumeratedValue>
                <enumeratedValue>
                  <name>1</name>
                  <description>Corresponding bit in PDORn is set to logic 1.</description>
                  <value>#1</value>
                </enumeratedValue>
              </enumeratedValues>
            </field>
          </fields>
        </register>
        <register>
          <name>PCOR</name>
          <description>Port Clear Output Register</description>
          <addressOffset>0x8</addressOffset>
          <size>32</size>
          <access>write-only</access>
          <resetValue>0</resetValue>
          <resetMask>0xFFFFFFFF</resetMask>
          <fields>
            <field>
              <name>PTCO</name>
              <description>Port Clear Output</description>
              <bitOffset>0</bitOffset>
              <bitWidth>32</bitWidth>
              <access>write-only</access>
              <enumeratedValues>
                <enumeratedValue>
                  <name>0</name>
                  <description>Corresponding bit in PDORn does not change.</description>
                  <value>#0</value>
                </enumeratedValue>
                <enumeratedValue>
                  <name>1</name>
                  <description>Corresponding bit in PDORn is cleared to logic 0.</description>
                  <value>#1</value>
                </enumeratedValue>
              </enumeratedValues>
            </field>
          </fields>
        </register>
        <register>
          <name>PTOR</name>
          <description>Port Toggle Output Register</description>
          <addressOffset>0xC</addressOffset>
          <size>32</size>
          <access>write-only</access>
          <resetValue>0</resetValue>
          <resetMask>0xFFFFFFFF</resetMask>
          <fields>
            <field>
              <name>PTTO</name>
              <description>Port Toggle Output</description>
              <bitOffset>0</bitOffset>
              <bitWidth>32</bitWidth>
              <access>write-only</access>
              <enumeratedValues>
                <enumeratedValue>
                  <name>0</name>
                  <description>Corresponding bit in PDORn does not change.</description>
                  <value>#0</value>
                </enumeratedValue>
                <enumeratedValue>
                  <name>1</name>
                  <description>Corresponding bit in PDORn is set to the inverse of its existing logic state.</description>
                  <value>#1</value>
                </enumeratedValue>
              </enumeratedValues>
            </field>
          </fields>
        </register>
        <register>
          <name>PDIR</name>
          <description>Port Data Input Register</description>
          <addressOffset>0x10</addressOffset>
          <size>32</size>
          <access>read-only</access>
          <resetValue>0</resetValue>
          <resetMask>0xFFFFFFFF</resetMask>
          <fields>
            <field>
              <name>PDI</name>
              <description>Port Data Input</description>
              <bitOffset>0</bitOffset>
              <bitWidth>32</bitWidth>
              <access>read-only</access>
              <enumeratedValues>
                <enumeratedValue>
                  <name>0</name>
                  <description>Pin logic level is logic 0, or is not configured for use by digital function.</description>
                  <value>#0</value>
                </enumeratedValue>
                <enumeratedValue>
                  <name>1</name>
                  <description>Pin logic level is logic 1.</description>
                  <value>#1</value>
                </enumeratedValue>
              </enumeratedValues>
            </field>
          </fields>
        </register>
        <register>
          <name>PDDR</name>
          <description>Port Data Direction Register</description>
          <addressOffset>0x14</addressOffset>
          <size>32</size>
          <access>read-write</access>
          <resetValue>0</resetValue>
          <resetMask>0xFFFFFFFF</resetMask>
          <fields>
            <field>
              <name>PDD</name>
              <description>Port Data Direction</description>
              <bitOffset>0</bitOffset>
              <bitWidth>32</bitWidth>
              <access>read-write</access>
              <enumeratedValues>
                <enumeratedValue>
                  <name>0</name>
                  <description>Pin is configured as general-purpose input, for the GPIO function.</description>
                  <value>#0</value>
                </enumeratedValue>
                <enumeratedValue>
                  <name>1</name>
                  <description>Pin is configured as general-purpose output, for the GPIO function.</description>
                  <value>#1</value>
                </enumeratedValue>
              </enumeratedValues>
            </field>
          </fields>
        </register>
      </registers>
    </peripheral>
    <peripheral>
      <name>MTB</name>
      <description>Micro Trace Buffer</description>
      <prependToName>MTB_</prependToName>
      <baseAddress>0xF0000000</baseAddress>
      <addressBlock>
        <offset>0</offset>
        <size>0x1000</size>
        <usage>registers</usage>
      </addressBlock>
      <registers>
        <register>
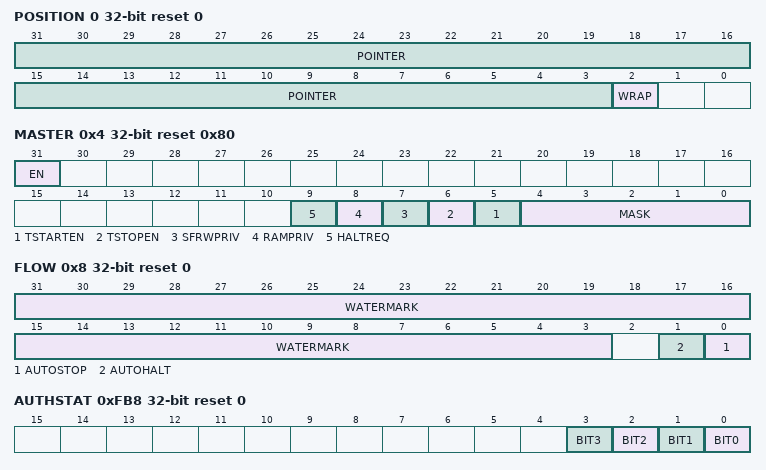
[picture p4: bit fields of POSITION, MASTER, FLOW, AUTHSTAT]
          <name>POSITION</name>
          <description>MTB Position Register</description>
          <addressOffset>0</addressOffset>
          <size>32</size>
          <access>read-write</access>
          <resetValue>0</resetValue>
          <resetMask>0x3</resetMask>
          <fields>
            <field>
              <name>WRAP</name>
              <description>This field is set to 1 automatically when the POINTER value wraps as determined by the MTB_MASTER[MASK] field in the MASTER Trace Control Register</description>
              <bitOffset>2</bitOffset>
              <bitWidth>1</bitWidth>
              <access>read-write</access>
            </field>
            <field>
              <name>POINTER</name>
              <description>Trace Packet Address Pointer[28:0]</description>
              <bitOffset>3</bitOffset>
              <bitWidth>29</bitWidth>
              <access>read-write</access>
            </field>
          </fields>
        </register>
        <register>
          <name>MASTER</name>
          <description>MTB Master Register</description>
          <addressOffset>0x4</addressOffset>
          <size>32</size>
          <access>read-write</access>
          <resetValue>0x80</resetValue>
          <resetMask>0xFFFFFFE0</resetMask>
          <fields>
            <field>
              <name>MASK</name>
              <description>Mask</description>
              <bitOffset>0</bitOffset>
              <bitWidth>5</bitWidth>
              <access>read-write</access>
            </field>
            <field>
              <name>TSTARTEN</name>
              <description>Trace Start Input Enable</description>
              <bitOffset>5</bitOffset>
              <bitWidth>1</bitWidth>
              <access>read-write</access>
            </field>
            <field>
              <name>TSTOPEN</name>
              <description>Trace Stop Input Enable</description>
              <bitOffset>6</bitOffset>
              <bitWidth>1</bitWidth>
              <access>read-write</access>
            </field>
            <field>
              <name>SFRWPRIV</name>
              <description>Special Function Register Write Privilege</description>
              <bitOffset>7</bitOffset>
              <bitWidth>1</bitWidth>
              <access>read-write</access>
            </field>
            <field>
              <name>RAMPRIV</name>
              <description>RAM Privilege</description>
              <bitOffset>8</bitOffset>
              <bitWidth>1</bitWidth>
              <access>read-write</access>
            </field>
            <field>
              <name>HALTREQ</name>
              <description>Halt Request</description>
              <bitOffset>9</bitOffset>
              <bitWidth>1</bitWidth>
              <access>read-write</access>
            </field>
            <field>
              <name>EN</name>
              <description>Main Trace Enable</description>
              <bitOffset>31</bitOffset>
              <bitWidth>1</bitWidth>
              <access>read-write</access>
            </field>
          </fields>
        </register>
        <register>
          <name>FLOW</name>
          <description>MTB Flow Register</description>
          <addressOffset>0x8</addressOffset>
          <size>32</size>
          <access>read-write</access>
          <resetValue>0</resetValue>
          <resetMask>0x4</resetMask>
          <fields>
            <field>
              <name>AUTOSTOP</name>
              <description>If this field is 1 and WATERMARK is equal to MTB_POSITION[POINTER], then MTB_MASTER[EN] is automatically set to 0</description>
              <bitOffset>0</bitOffset>
              <bitWidth>1</bitWidth>
              <access>read-write</access>
            </field>
            <field>
              <name>AUTOHALT</name>
              <description>If this field is 1 and WATERMARK is equal to MTB_POSITION[POINTER], then MTB_MASTER[HALTREQ] is automatically set to 1</description>
              <bitOffset>1</bitOffset>
              <bitWidth>1</bitWidth>
              <access>read-write</access>
            </field>
            <field>
              <name>WATERMARK</name>
              <description>WATERMARK[28:0]</description>
              <bitOffset>3</bitOffset>
              <bitWidth>29</bitWidth>
              <access>read-write</access>
            </field>
          </fields>
        </register>
        <register>
          <name>BASE</name>
          <description>MTB Base Register</description>
          <addressOffset>0xC</addressOffset>
          <size>32</size>
          <access>read-only</access>
          <resetValue>0</resetValue>
          <resetMask>0</resetMask>
          <fields>
            <field>
              <name>BASEADDR</name>
              <description>This value is defined with a hardwired signal and the expression: 0x2000_0000 - (RAM_Size/4)</description>
              <bitOffset>0</bitOffset>
              <bitWidth>32</bitWidth>
              <access>read-only</access>
            </field>
          </fields>
        </register>
        <register>
          <name>MODECTRL</name>
          <description>Integration Mode Control Register</description>
          <addressOffset>0xF00</addressOffset>
          <size>32</size>
          <access>read-only</access>
          <resetValue>0</resetValue>
          <resetMask>0xFFFFFFFF</resetMask>
          <fields>
            <field>
              <name>MODECTRL</name>
              <description>Hardwired to 0x0000_0000</description>
              <bitOffset>0</bitOffset>
              <bitWidth>32</bitWidth>
              <access>read-only</access>
            </field>
          </fields>
        </register>
        <register>
          <name>TAGSET</name>
          <description>Claim TAG Set Register</description>
          <addressOffset>0xFA0</addressOffset>
          <size>32</size>
          <access>read-only</access>
          <resetValue>0</resetValue>
          <resetMask>0xFFFFFFFF</resetMask>
          <fields>
            <field>
              <name>TAGSET</name>
              <description>Hardwired to 0x0000_0000</description>
              <bitOffset>0</bitOffset>
              <bitWidth>32</bitWidth>
              <access>read-only</access>
            </field>
          </fields>
        </register>
        <register>
          <name>TAGCLEAR</name>
          <description>Claim TAG Clear Register</description>
          <addressOffset>0xFA4</addressOffset>
          <size>32</size>
          <access>read-only</access>
          <resetValue>0</resetValue>
          <resetMask>0xFFFFFFFF</resetMask>
          <fields>
            <field>
              <name>TAGCLEAR</name>
              <description>Hardwired to 0x0000_0000</description>
              <bitOffset>0</bitOffset>
              <bitWidth>32</bitWidth>
              <access>read-only</access>
            </field>
          </fields>
        </register>
        <register>
          <name>LOCKACCESS</name>
          <description>Lock Access Register</description>
          <addressOffset>0xFB0</addressOffset>
          <size>32</size>
          <access>read-only</access>
          <resetValue>0</resetValue>
          <resetMask>0xFFFFFFFF</resetMask>
          <fields>
            <field>
              <name>LOCKACCESS</name>
              <description>Hardwired to 0x0000_0000</description>
              <bitOffset>0</bitOffset>
              <bitWidth>32</bitWidth>
              <access>read-only</access>
            </field>
          </fields>
        </register>
        <register>
          <name>LOCKSTAT</name>
          <description>Lock Status Register</description>
          <addressOffset>0xFB4</addressOffset>
          <size>32</size>
          <access>read-only</access>
          <resetValue>0</resetValue>
          <resetMask>0xFFFFFFFF</resetMask>
          <fields>
            <field>
              <name>LOCKSTAT</name>
              <description>Hardwired to 0x0000_0000</description>
              <bitOffset>0</bitOffset>
              <bitWidth>32</bitWidth>
              <access>read-only</access>
            </field>
          </fields>
        </register>
        <register>
          <name>AUTHSTAT</name>
          <description>Authentication Status Register</description>
          <addressOffset>0xFB8</addressOffset>
          <size>32</size>
          <access>read-only</access>
          <resetValue>0</resetValue>
          <resetMask>0xFFFFFFFF</resetMask>
          <fields>
            <field>
              <name>BIT0</name>
              <description>Connected to DBGEN.</description>
              <bitOffset>0</bitOffset>
              <bitWidth>1</bitWidth>
              <access>read-only</access>
            </field>
            <field>
              <name>BIT1</name>
              <description>Hardwired to 1.</description>
              <bitOffset>1</bitOffset>
              <bitWidth>1</bitWidth>
              <access>read-only</access>
            </field>
            <field>
              <name>BIT2</name>
              <description>Connected to NIDEN or DBGEN signal.</description>
              <bitOffset>2</bitOffset>
              <bitWidth>1</bitWidth>
              <access>read-only</access>
            </field>
            <field>
              <name>BIT3</name>
              <description>Hardwired to 1.</description>
              <bitOffset>3</bitOffset>
              <bitWidth>1</bitWidth>
              <access>read-only</access>
            </field>
          </fields>
        </register>
        <register>
          <name>DEVICEARCH</name>
          <description>Device Architecture Register</description>
          <addressOffset>0xFBC</addressOffset>
          <size>32</size>
          <access>read-only</access>
          <resetValue>0x47700A31</resetValue>
          <resetMask>0xFFFFFFFF</resetMask>
          <fields>
            <field>
              <name>DEVICEARCH</name>
              <description>Hardwired to 0x4770_0A31.</description>
              <bitOffset>0</bitOffset>
              <bitWidth>32</bitWidth>
              <access>read-only</access>
            </field>
          </fields>
        </register>
        <register>
          <name>DEVICECFG</name>
          <description>Device Configuration Register</description>
          <addressOffset>0xFC8</addressOffset>
          <size>32</size>
          <access>read-only</access>
          <resetValue>0</resetValue>
          <resetMask>0xFFFFFFFF</resetMask>
          <fields>
            <field>
              <name>DEVICECFG</name>
              <description>Hardwired to 0x0000_0000.</description>
              <bitOffset>0</bitOffset>
              <bitWidth>32</bitWidth>
              <access>read-only</access>
            </field>
          </fields>
        </register>
        <register>
          <name>DEVICETYPID</name>
          <description>Device Type Identifier Register</description>
          <addressOffset>0xFCC</addressOffset>
          <size>32</size>
          <access>read-only</access>
          <resetValue>0x31</resetValue>
          <resetMask>0xFFFFFFFF</resetMask>
          <fields>
            <field>
              <name>DEVICETYPID</name>
              <description>Hardwired to 0x0000_0031.</description>
              <bitOffset>0</bitOffset>
              <bitWidth>32</bitWidth>
              <access>read-only</access>
            </field>
          </fields>
        </register>
        <register>
          <dim>8</dim>
          <dimIncrement>0x4</dimIncrement>
          <dimIndex>4,5,6,7,0,1,2,3</dimIndex>
          <name>PERIPHID%s</name>
          <description>Peripheral ID Register</description>
          <addressOffset>0xFD0</addressOffset>
          <size>32</size>
          <access>read-only</access>
          <resetValue>0</resetValue>
          <resetMask>0</resetMask>
          <fields>
            <field>
              <name>PERIPHID</name>
              <description>Peripheral ID4 is hardwired to 0x0000_0004; ID0 to 0x0000_0032; ID1 to 0x0000_00B9; ID2 to 0x0000_000B; and all the others to 0x0000_0000</description>
              <bitOffset>0</bitOffset>
              <bitWidth>32</bitWidth>
              <access>read-only</access>
            </field>
          </fields>
        </register>
        <register>
          <dim>4</dim>
          <dimIncrement>0x4</dimIncrement>
          <dimIndex>0,1,2,3</dimIndex>
          <name>COMPID%s</name>
          <description>Component ID Register</description>
          <addressOffset>0xFF0</addressOffset>
          <size>32</size>
          <access>read-only</access>
          <resetValue>0</resetValue>
          <resetMask>0</resetMask>
          <fields>
            <field>
              <name>COMPID</name>
              <description>Component ID</description>
              <bitOffset>0</bitOffset>
              <bitWidth>32</bitWidth>
              <access>read-only</access>
            </field>
          </fields>
        </register>
      </registers>
    </peripheral>
    <peripheral>
      <name>MTBDWT</name>
      <description>MTB data watchpoint and trace</description>
      <prependToName>MTBDWT_</prependToName>
      <baseAddress>0xF0001000</baseAddress>
      <addressBlock>
        <offset>0</offset>
        <size>0x1000</size>
        <usage>registers</usage>
      </addressBlock>
      <registers>
        <register>
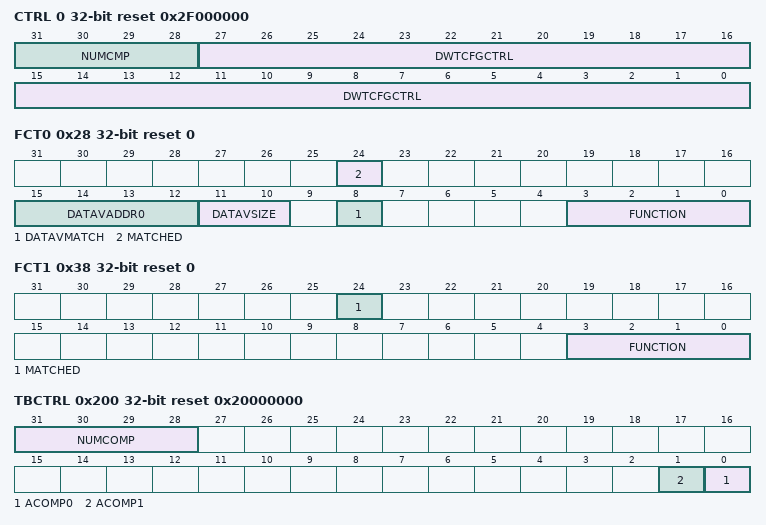
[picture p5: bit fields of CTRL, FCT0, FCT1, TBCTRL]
          <name>CTRL</name>
          <description>MTB DWT Control Register</description>
          <addressOffset>0</addressOffset>
          <size>32</size>
          <access>read-only</access>
          <resetValue>0x2F000000</resetValue>
          <resetMask>0xFFFFFFFF</resetMask>
          <fields>
            <field>
              <name>DWTCFGCTRL</name>
              <description>DWT configuration controls</description>
              <bitOffset>0</bitOffset>
              <bitWidth>28</bitWidth>
              <access>read-only</access>
            </field>
            <field>
              <name>NUMCMP</name>
              <description>Number of comparators</description>
              <bitOffset>28</bitOffset>
              <bitWidth>4</bitWidth>
              <access>read-only</access>
            </field>
          </fields>
        </register>
        <register>
          <dim>2</dim>
          <dimIncrement>0x10</dimIncrement>
          <dimIndex>0,1</dimIndex>
          <name>COMP%s</name>
          <description>MTB_DWT Comparator Register</description>
          <addressOffset>0x20</addressOffset>
          <size>32</size>
          <access>read-write</access>
          <resetValue>0</resetValue>
          <resetMask>0xFFFFFFFF</resetMask>
          <fields>
            <field>
              <name>COMP</name>
              <description>Reference value for comparison</description>
              <bitOffset>0</bitOffset>
              <bitWidth>32</bitWidth>
              <access>read-write</access>
            </field>
          </fields>
        </register>
        <register>
          <dim>2</dim>
          <dimIncrement>0x10</dimIncrement>
          <dimIndex>0,1</dimIndex>
          <name>MASK%s</name>
          <description>MTB_DWT Comparator Mask Register</description>
          <addressOffset>0x24</addressOffset>
          <size>32</size>
          <access>read-write</access>
          <resetValue>0</resetValue>
          <resetMask>0xFFFFFFFF</resetMask>
          <fields>
            <field>
              <name>MASK</name>
              <description>MASK</description>
              <bitOffset>0</bitOffset>
              <bitWidth>5</bitWidth>
              <access>read-write</access>
            </field>
          </fields>
        </register>
        <register>
          <name>FCT0</name>
          <description>MTB_DWT Comparator Function Register 0</description>
          <addressOffset>0x28</addressOffset>
          <size>32</size>
          <access>read-write</access>
          <resetValue>0</resetValue>
          <resetMask>0xFFFFFFFF</resetMask>
          <fields>
            <field>
              <name>FUNCTION</name>
              <description>Function</description>
              <bitOffset>0</bitOffset>
              <bitWidth>4</bitWidth>
              <access>read-write</access>
              <enumeratedValues>
                <enumeratedValue>
                  <name>0000</name>
                  <description>Disabled.</description>
                  <value>#0000</value>
                </enumeratedValue>
                <enumeratedValue>
                  <name>0100</name>
                  <description>Instruction fetch.</description>
                  <value>#0100</value>
                </enumeratedValue>
                <enumeratedValue>
                  <name>0101</name>
                  <description>Data operand read.</description>
                  <value>#0101</value>
                </enumeratedValue>
                <enumeratedValue>
                  <name>0110</name>
                  <description>Data operand write.</description>
                  <value>#0110</value>
                </enumeratedValue>
                <enumeratedValue>
                  <name>0111</name>
                  <description>Data operand (read + write).</description>
                  <value>#0111</value>
                </enumeratedValue>
              </enumeratedValues>
            </field>
            <field>
              <name>DATAVMATCH</name>
              <description>Data Value Match</description>
              <bitOffset>8</bitOffset>
              <bitWidth>1</bitWidth>
              <access>read-write</access>
              <enumeratedValues>
                <enumeratedValue>
                  <name>0</name>
                  <description>Perform address comparison.</description>
                  <value>#0</value>
                </enumeratedValue>
                <enumeratedValue>
                  <name>1</name>
                  <description>Perform data value comparison.</description>
                  <value>#1</value>
                </enumeratedValue>
              </enumeratedValues>
            </field>
            <field>
              <name>DATAVSIZE</name>
              <description>Data Value Size</description>
              <bitOffset>10</bitOffset>
              <bitWidth>2</bitWidth>
              <access>read-write</access>
              <enumeratedValues>
                <enumeratedValue>
                  <name>00</name>
                  <description>Byte.</description>
                  <value>#00</value>
                </enumeratedValue>
                <enumeratedValue>
                  <name>01</name>
                  <description>Halfword.</description>
                  <value>#01</value>
                </enumeratedValue>
                <enumeratedValue>
                  <name>10</name>
                  <description>Word.</description>
                  <value>#10</value>
                </enumeratedValue>
                <enumeratedValue>
                  <name>11</name>
                  <description>Reserved. Any attempts to use this value results in UNPREDICTABLE behavior.</description>
                  <value>#11</value>
                </enumeratedValue>
              </enumeratedValues>
            </field>
            <field>
              <name>DATAVADDR0</name>
              <description>Data Value Address 0</description>
              <bitOffset>12</bitOffset>
              <bitWidth>4</bitWidth>
              <access>read-write</access>
            </field>
            <field>
              <name>MATCHED</name>
              <description>Comparator match</description>
              <bitOffset>24</bitOffset>
              <bitWidth>1</bitWidth>
              <access>read-only</access>
              <enumeratedValues>
                <enumeratedValue>
                  <name>0</name>
                  <description>No match.</description>
                  <value>#0</value>
                </enumeratedValue>
                <enumeratedValue>
                  <name>1</name>
                  <description>Match occurred.</description>
                  <value>#1</value>
                </enumeratedValue>
              </enumeratedValues>
            </field>
          </fields>
        </register>
        <register>
          <name>FCT1</name>
          <description>MTB_DWT Comparator Function Register 1</description>
          <addressOffset>0x38</addressOffset>
          <size>32</size>
          <access>read-write</access>
          <resetValue>0</resetValue>
          <resetMask>0xFFFFFFFF</resetMask>
          <fields>
            <field>
              <name>FUNCTION</name>
              <description>Function</description>
              <bitOffset>0</bitOffset>
              <bitWidth>4</bitWidth>
              <access>read-write</access>
              <enumeratedValues>
                <enumeratedValue>
                  <name>0000</name>
                  <description>Disabled.</description>
                  <value>#0000</value>
                </enumeratedValue>
                <enumeratedValue>
                  <name>0100</name>
                  <description>Instruction fetch.</description>
                  <value>#0100</value>
                </enumeratedValue>
                <enumeratedValue>
                  <name>0101</name>
                  <description>Data operand read.</description>
                  <value>#0101</value>
                </enumeratedValue>
                <enumeratedValue>
                  <name>0110</name>
                  <description>Data operand write.</description>
                  <value>#0110</value>
                </enumeratedValue>
                <enumeratedValue>
                  <name>0111</name>
                  <description>Data operand (read + write).</description>
                  <value>#0111</value>
                </enumeratedValue>
              </enumeratedValues>
            </field>
            <field>
              <name>MATCHED</name>
              <description>Comparator match</description>
              <bitOffset>24</bitOffset>
              <bitWidth>1</bitWidth>
              <access>read-only</access>
              <enumeratedValues>
                <enumeratedValue>
                  <name>0</name>
                  <description>No match.</description>
                  <value>#0</value>
                </enumeratedValue>
                <enumeratedValue>
                  <name>1</name>
                  <description>Match occurred.</description>
                  <value>#1</value>
                </enumeratedValue>
              </enumeratedValues>
            </field>
          </fields>
        </register>
        <register>
          <name>TBCTRL</name>
          <description>MTB_DWT Trace Buffer Control Register</description>
          <addressOffset>0x200</addressOffset>
          <size>32</size>
          <access>read-write</access>
          <resetValue>0x20000000</resetValue>
          <resetMask>0xFFFFFFFF</resetMask>
          <fields>
            <field>
              <name>ACOMP0</name>
              <description>Action based on Comparator 0 match</description>
              <bitOffset>0</bitOffset>
              <bitWidth>1</bitWidth>
              <access>read-write</access>
              <enumeratedValues>
                <enumeratedValue>
                  <name>0</name>
                  <description>Trigger TSTOP based on the assertion of MTBDWT_FCT0[MATCHED].</description>
                  <value>#0</value>
                </enumeratedValue>
                <enumeratedValue>
                  <name>1</name>
                  <description>Trigger TSTART based on the assertion of MTBDWT_FCT0[MATCHED].</description>
                  <value>#1</value>
                </enumeratedValue>
              </enumeratedValues>
            </field>
            <field>
              <name>ACOMP1</name>
              <description>Action based on Comparator 1 match</description>
              <bitOffset>1</bitOffset>
              <bitWidth>1</bitWidth>
              <access>read-write</access>
              <enumeratedValues>
                <enumeratedValue>
                  <name>0</name>
                  <description>Trigger TSTOP based on the assertion of MTBDWT_FCT1[MATCHED].</description>
                  <value>#0</value>
                </enumeratedValue>
                <enumeratedValue>
                  <name>1</name>
                  <description>Trigger TSTART based on the assertion of MTBDWT_FCT1[MATCHED].</description>
                  <value>#1</value>
                </enumeratedValue>
              </enumeratedValues>
            </field>
            <field>
              <name>NUMCOMP</name>
              <description>Number of Comparators</description>
              <bitOffset>28</bitOffset>
              <bitWidth>4</bitWidth>
              <access>read-only</access>
            </field>
          </fields>
        </register>
        <register>
          <name>DEVICECFG</name>
          <description>Device Configuration Register</description>
          <addressOffset>0xFC8</addressOffset>
          <size>32</size>
          <access>read-only</access>
          <resetValue>0</resetValue>
          <resetMask>0xFFFFFFFF</resetMask>
          <fields>
            <field>
              <name>DEVICECFG</name>
              <description>Hardwired to 0x0000_0000.</description>
              <bitOffset>0</bitOffset>
              <bitWidth>32</bitWidth>
              <access>read-only</access>
            </field>
          </fields>
        </register>
        <register>
          <name>DEVICETYPID</name>
          <description>Device Type Identifier Register</description>
          <addressOffset>0xFCC</addressOffset>
          <size>32</size>
          <access>read-only</access>
          <resetValue>0x4</resetValue>
          <resetMask>0xFFFFFFFF</resetMask>
          <fields>
            <field>
              <name>DEVICETYPID</name>
              <description>Hardwired to 0x0000_0004.</description>
              <bitOffset>0</bitOffset>
              <bitWidth>32</bitWidth>
              <access>read-only</access>
            </field>
          </fields>
        </register>
        <register>
          <dim>8</dim>
          <dimIncrement>0x4</dimIncrement>
          <dimIndex>4,5,6,7,0,1,2,3</dimIndex>
          <name>PERIPHID%s</name>
          <description>Peripheral ID Register</description>
          <addressOffset>0xFD0</addressOffset>
          <size>32</size>
          <access>read-only</access>
          <resetValue>0</resetValue>
          <resetMask>0</resetMask>
          <fields>
            <field>
              <name>PERIPHID</name>
              <description>Peripheral ID1 is hardwired to 0x0000_00E0; ID2 to 0x0000_0008; and all the others to 0x0000_0000.</description>
              <bitOffset>0</bitOffset>
              <bitWidth>32</bitWidth>
              <access>read-only</access>
            </field>
          </fields>
        </register>
        <register>
          <dim>4</dim>
          <dimIncrement>0x4</dimIncrement>
          <dimIndex>0,1,2,3</dimIndex>
          <name>COMPID%s</name>
          <description>Component ID Register</description>
          <addressOffset>0xFF0</addressOffset>
          <size>32</size>
          <access>read-only</access>
          <resetValue>0</resetValue>
          <resetMask>0</resetMask>
          <fields>
            <field>
              <name>COMPID</name>
              <description>Component ID</description>
              <bitOffset>0</bitOffset>
              <bitWidth>32</bitWidth>
              <access>read-only</access>
            </field>
          </fields>
        </register>
      </registers>
    </peripheral>
    <peripheral>
      <name>ROM</name>
      <description>System ROM</description>
      <prependToName>ROM_</prependToName>
      <baseAddress>0xF0002000</baseAddress>
      <addressBlock>
        <offset>0</offset>
        <size>0x1000</size>
        <usage>registers</usage>
      </addressBlock>
      <registers>
        <register>
          <dim>3</dim>
          <dimIncrement>0x4</dimIncrement>
          <dimIndex>0,1,2</dimIndex>
          <name>ENTRY%s</name>
          <description>Entry</description>
          <addressOffset>0</addressOffset>
          <size>32</size>
          <access>read-only</access>
          <resetValue>0</resetValue>
          <resetMask>0</resetMask>
          <fields>
            <field>
              <name>ENTRY</name>
              <description>ENTRY</description>
              <bitOffset>0</bitOffset>
              <bitWidth>32</bitWidth>
              <access>read-only</access>
            </field>
          </fields>
        </register>
        <register>
          <name>TABLEMARK</name>
          <description>End of Table Marker Register</description>
          <addressOffset>0xC</addressOffset>
          <size>32</size>
          <access>read-only</access>
          <resetValue>0</resetValue>
          <resetMask>0xFFFFFFFF</resetMask>
          <fields>
            <field>
              <name>MARK</name>
              <description>Hardwired to 0x0000_0000</description>
              <bitOffset>0</bitOffset>
              <bitWidth>32</bitWidth>
              <access>read-only</access>
            </field>
          </fields>
        </register>
        <register>
          <name>SYSACCESS</name>
          <description>System Access Register</description>
          <addressOffset>0xFCC</addressOffset>
          <size>32</size>
          <access>read-only</access>
          <resetValue>0x1</resetValue>
          <resetMask>0xFFFFFFFF</resetMask>
          <fields>
            <field>
              <name>SYSACCESS</name>
              <description>Hardwired to 0x0000_0001</description>
              <bitOffset>0</bitOffset>
              <bitWidth>32</bitWidth>
              <access>read-only</access>
            </field>
          </fields>
        </register>
        <register>
          <dim>8</dim>
          <dimIncrement>0x4</dimIncrement>
          <dimIndex>4,5,6,7,0,1,2,3</dimIndex>
          <name>PERIPHID%s</name>
          <description>Peripheral ID Register</description>
          <addressOffset>0xFD0</addressOffset>
          <size>32</size>
          <access>read-only</access>
          <resetValue>0</resetValue>
          <resetMask>0</resetMask>
          <fields>
            <field>
              <name>PERIPHID</name>
              <description>Peripheral ID1 is hardwired to 0x0000_00E0; ID2 to 0x0000_0008; and all the others to 0x0000_0000.</description>
              <bitOffset>0</bitOffset>
              <bitWidth>32</bitWidth>
              <access>read-only</access>
            </field>
          </fields>
        </register>
        <register>
          <dim>4</dim>
          <dimIncrement>0x4</dimIncrement>
          <dimIndex>0,1,2,3</dimIndex>
          <name>COMPID%s</name>
          <description>Component ID Register</description>
          <addressOffset>0xFF0</addressOffset>
          <size>32</size>
          <access>read-only</access>
          <resetValue>0</resetValue>
          <resetMask>0</resetMask>
          <fields>
            <field>
              <name>COMPID</name>
              <description>Component ID</description>
              <bitOffset>0</bitOffset>
              <bitWidth>32</bitWidth>
              <access>read-only</access>
            </field>
          </fields>
        </register>
      </registers>
    </peripheral>
    <peripheral>
      <name>MCM</name>
      <description>Core Platform Miscellaneous Control Module</description>
      <prependToName>MCM_</prependToName>
      <baseAddress>0xF0003000</baseAddress>
      <addressBlock>
        <offset>0x8</offset>
        <size>0x3C</size>
        <usage>registers</usage>
      </addressBlock>
      <registers>
        <register>
          <name>PLASC</name>
          <description>Crossbar Switch (AXBS) Slave Configuration</description>
          <addressOffset>0x8</addressOffset>
          <size>16</size>
          <access>read-only</access>
          <resetValue>0x7</resetValue>
          <resetMask>0xFFFF</resetMask>
          <fields>
            <field>
              <name>ASC</name>
              <description>Each bit in the ASC field indicates whether there is a corresponding connection to the crossbar switch&apos;s slave input port.</description>
              <bitOffset>0</bitOffset>
              <bitWidth>8</bitWidth>
              <access>read-only</access>
              <enumeratedValues>
                <enumeratedValue>
                  <name>0</name>
                  <description>A bus slave connection to AXBS input port n is absent.</description>
                  <value>#0</value>
                </enumeratedValue>
                <enumeratedValue>
                  <name>1</name>
                  <description>A bus slave connection to AXBS input port n is present.</description>
                  <value>#1</value>
                </enumeratedValue>
              </enumeratedValues>
            </field>
          </fields>
        </register>
        <register>
          <name>PLAMC</name>
          <description>Crossbar Switch (AXBS) Master Configuration</description>
          <addressOffset>0xA</addressOffset>
          <size>16</size>
          <access>read-only</access>
          <resetValue>0xD</resetValue>
          <resetMask>0xFFFF</resetMask>
          <fields>
            <field>
              <name>AMC</name>
              <description>Each bit in the AMC field indicates whether there is a corresponding connection to the AXBS master input port.</description>
              <bitOffset>0</bitOffset>
              <bitWidth>8</bitWidth>
              <access>read-only</access>
              <enumeratedValues>
                <enumeratedValue>
                  <name>0</name>
                  <description>A bus master connection to AXBS input port n is absent</description>
                  <value>#0</value>
                </enumeratedValue>
                <enumeratedValue>
                  <name>1</name>
                  <description>A bus master connection to AXBS input port n is present</description>
                  <value>#1</value>
                </enumeratedValue>
              </enumeratedValues>
            </field>
          </fields>
        </register>
        <register>
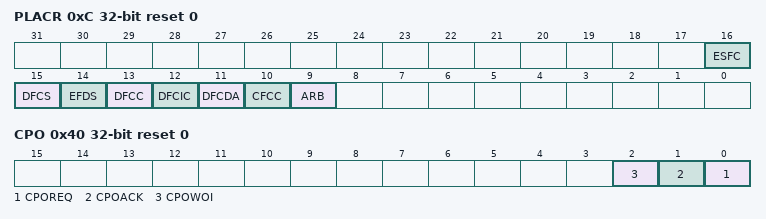
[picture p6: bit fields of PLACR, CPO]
          <name>PLACR</name>
          <description>Platform Control Register</description>
          <addressOffset>0xC</addressOffset>
          <size>32</size>
          <access>read-write</access>
          <resetValue>0</resetValue>
          <resetMask>0xFFFFFFFF</resetMask>
          <fields>
            <field>
              <name>ARB</name>
              <description>Arbitration select</description>
              <bitOffset>9</bitOffset>
              <bitWidth>1</bitWidth>
              <access>read-write</access>
              <enumeratedValues>
                <enumeratedValue>
                  <name>0</name>
                  <description>Fixed-priority arbitration for the crossbar masters</description>
                  <value>#0</value>
                </enumeratedValue>
                <enumeratedValue>
                  <name>1</name>
                  <description>Round-robin arbitration for the crossbar masters</description>
                  <value>#1</value>
                </enumeratedValue>
              </enumeratedValues>
            </field>
            <field>
              <name>CFCC</name>
              <description>Clear Flash Controller Cache</description>
              <bitOffset>10</bitOffset>
              <bitWidth>1</bitWidth>
              <access>write-only</access>
            </field>
            <field>
              <name>DFCDA</name>
              <description>Disable Flash Controller Data Caching</description>
              <bitOffset>11</bitOffset>
              <bitWidth>1</bitWidth>
              <access>read-write</access>
              <enumeratedValues>
                <enumeratedValue>
                  <name>0</name>
                  <description>Enable flash controller data caching</description>
                  <value>#0</value>
                </enumeratedValue>
                <enumeratedValue>
                  <name>1</name>
                  <description>Disable flash controller data caching.</description>
                  <value>#1</value>
                </enumeratedValue>
              </enumeratedValues>
            </field>
            <field>
              <name>DFCIC</name>
              <description>Disable Flash Controller Instruction Caching</description>
              <bitOffset>12</bitOffset>
              <bitWidth>1</bitWidth>
              <access>read-write</access>
              <enumeratedValues>
                <enumeratedValue>
                  <name>0</name>
                  <description>Enable flash controller instruction caching.</description>
                  <value>#0</value>
                </enumeratedValue>
                <enumeratedValue>
                  <name>1</name>
                  <description>Disable flash controller instruction caching.</description>
                  <value>#1</value>
                </enumeratedValue>
              </enumeratedValues>
            </field>
            <field>
              <name>DFCC</name>
              <description>Disable Flash Controller Cache</description>
              <bitOffset>13</bitOffset>
              <bitWidth>1</bitWidth>
              <access>read-write</access>
              <enumeratedValues>
                <enumeratedValue>
                  <name>0</name>
                  <description>Enable flash controller cache.</description>
                  <value>#0</value>
                </enumeratedValue>
                <enumeratedValue>
                  <name>1</name>
                  <description>Disable flash controller cache.</description>
                  <value>#1</value>
                </enumeratedValue>
              </enumeratedValues>
            </field>
            <field>
              <name>EFDS</name>
              <description>Enable Flash Data Speculation</description>
              <bitOffset>14</bitOffset>
              <bitWidth>1</bitWidth>
              <access>read-write</access>
              <enumeratedValues>
                <enumeratedValue>
                  <name>0</name>
                  <description>Disable flash data speculation.</description>
                  <value>#0</value>
                </enumeratedValue>
                <enumeratedValue>
                  <name>1</name>
                  <description>Enable flash data speculation.</description>
                  <value>#1</value>
                </enumeratedValue>
              </enumeratedValues>
            </field>
            <field>
              <name>DFCS</name>
              <description>Disable Flash Controller Speculation</description>
              <bitOffset>15</bitOffset>
              <bitWidth>1</bitWidth>
              <access>read-write</access>
              <enumeratedValues>
                <enumeratedValue>
                  <name>0</name>
                  <description>Enable flash controller speculation.</description>
                  <value>#0</value>
                </enumeratedValue>
                <enumeratedValue>
                  <name>1</name>
                  <description>Disable flash controller speculation.</description>
                  <value>#1</value>
                </enumeratedValue>
              </enumeratedValues>
            </field>
            <field>
              <name>ESFC</name>
              <description>Enable Stalling Flash Controller</description>
              <bitOffset>16</bitOffset>
              <bitWidth>1</bitWidth>
              <access>read-write</access>
              <enumeratedValues>
                <enumeratedValue>
                  <name>0</name>
                  <description>Disable stalling flash controller when flash is busy.</description>
                  <value>#0</value>
                </enumeratedValue>
                <enumeratedValue>
                  <name>1</name>
                  <description>Enable stalling flash controller when flash is busy.</description>
                  <value>#1</value>
                </enumeratedValue>
              </enumeratedValues>
            </field>
          </fields>
        </register>
        <register>
          <name>CPO</name>
          <description>Compute Operation Control Register</description>
          <addressOffset>0x40</addressOffset>
          <size>32</size>
          <access>read-write</access>
          <resetValue>0</resetValue>
          <resetMask>0xFFFFFFFF</resetMask>
          <fields>
            <field>
              <name>CPOREQ</name>
              <description>Compute Operation Request</description>
              <bitOffset>0</bitOffset>
              <bitWidth>1</bitWidth>
              <access>read-write</access>
              <enumeratedValues>
                <enumeratedValue>
                  <name>0</name>
                  <description>Request is cleared.</description>
                  <value>#0</value>
                </enumeratedValue>
                <enumeratedValue>
                  <name>1</name>
                  <description>Request Compute Operation.</description>
                  <value>#1</value>
                </enumeratedValue>
              </enumeratedValues>
            </field>
            <field>
              <name>CPOACK</name>
              <description>Compute Operation Acknowledge</description>
              <bitOffset>1</bitOffset>
              <bitWidth>1</bitWidth>
              <access>read-only</access>
              <enumeratedValues>
                <enumeratedValue>
                  <name>0</name>
                  <description>Compute operation entry has not completed or compute operation exit has completed.</description>
                  <value>#0</value>
                </enumeratedValue>
                <enumeratedValue>
                  <name>1</name>
                  <description>Compute operation entry has completed or compute operation exit has not completed.</description>
                  <value>#1</value>
                </enumeratedValue>
              </enumeratedValues>
            </field>
            <field>
              <name>CPOWOI</name>
              <description>Compute Operation Wake-up on Interrupt</description>
              <bitOffset>2</bitOffset>
              <bitWidth>1</bitWidth>
              <access>read-write</access>
              <enumeratedValues>
                <enumeratedValue>
                  <name>0</name>
                  <description>No effect.</description>
                  <value>#0</value>
                </enumeratedValue>
                <enumeratedValue>
                  <name>1</name>
                  <description>When set, the CPOREQ is cleared on any interrupt or exception vector fetch.</description>
                  <value>#1</value>
                </enumeratedValue>
              </enumeratedValues>
            </field>
          </fields>
        </register>
      </registers>
    </peripheral>
    <peripheral>
      <name>FGPIOA</name>
      <description>General Purpose Input/Output</description>
      <groupName>FGPIO</groupName>
      <prependToName>FGPIOA_</prependToName>
      <baseAddress>0xF8000000</baseAddress>
      <addressBlock>
        <offset>0</offset>
        <size>0x18</size>
        <usage>registers</usage>
      </addressBlock>
      <registers>
        <register>
          <name>PDOR</name>
          <description>Port Data Output Register</description>
          <addressOffset>0</addressOffset>
          <size>32</size>
          <access>read-write</access>
          <resetValue>0</resetValue>
          <resetMask>0xFFFFFFFF</resetMask>
          <fields>
            <field>
              <name>PDO</name>
              <description>Port Data Output</description>
              <bitOffset>0</bitOffset>
              <bitWidth>32</bitWidth>
              <access>read-write</access>
              <enumeratedValues>
                <enumeratedValue>
                  <name>0</name>
                  <description>Logic level 0 is driven on pin, provided pin is configured for general-purpose output.</description>
                  <value>#0</value>
                </enumeratedValue>
                <enumeratedValue>
                  <name>1</name>
                  <description>Logic level 1 is driven on pin, provided pin is configured for general-purpose output.</description>
                  <value>#1</value>
                </enumeratedValue>
              </enumeratedValues>
            </field>
          </fields>
        </register>
        <register>
          <name>PSOR</name>
          <description>Port Set Output Register</description>
          <addressOffset>0x4</addressOffset>
          <size>32</size>
          <access>write-only</access>
          <resetValue>0</resetValue>
          <resetMask>0xFFFFFFFF</resetMask>
          <fields>
            <field>
              <name>PTSO</name>
              <description>Port Set Output</description>
              <bitOffset>0</bitOffset>
              <bitWidth>32</bitWidth>
              <access>write-only</access>
              <enumeratedValues>
                <enumeratedValue>
                  <name>0</name>
                  <description>Corresponding bit in PDORn does not change.</description>
                  <value>#0</value>
                </enumeratedValue>
                <enumeratedValue>
                  <name>1</name>
                  <description>Corresponding bit in PDORn is set to logic 1.</description>
                  <value>#1</value>
                </enumeratedValue>
              </enumeratedValues>
            </field>
          </fields>
        </register>
        <register>
          <name>PCOR</name>
          <description>Port Clear Output Register</description>
          <addressOffset>0x8</addressOffset>
          <size>32</size>
          <access>write-only</access>
          <resetValue>0</resetValue>
          <resetMask>0xFFFFFFFF</resetMask>
          <fields>
            <field>
              <name>PTCO</name>
              <description>Port Clear Output</description>
              <bitOffset>0</bitOffset>
              <bitWidth>32</bitWidth>
              <access>write-only</access>
              <enumeratedValues>
                <enumeratedValue>
                  <name>0</name>
                  <description>Corresponding bit in PDORn does not change.</description>
                  <value>#0</value>
                </enumeratedValue>
                <enumeratedValue>
                  <name>1</name>
                  <description>Corresponding bit in PDORn is cleared to logic 0.</description>
                  <value>#1</value>
                </enumeratedValue>
              </enumeratedValues>
            </field>
          </fields>
        </register>
        <register>
          <name>PTOR</name>
          <description>Port Toggle Output Register</description>
          <addressOffset>0xC</addressOffset>
          <size>32</size>
          <access>write-only</access>
          <resetValue>0</resetValue>
          <resetMask>0xFFFFFFFF</resetMask>
          <fields>
            <field>
              <name>PTTO</name>
              <description>Port Toggle Output</description>
              <bitOffset>0</bitOffset>
              <bitWidth>32</bitWidth>
              <access>write-only</access>
              <enumeratedValues>
                <enumeratedValue>
                  <name>0</name>
                  <description>Corresponding bit in PDORn does not change.</description>
                  <value>#0</value>
                </enumeratedValue>
                <enumeratedValue>
                  <name>1</name>
                  <description>Corresponding bit in PDORn is set to the inverse of its existing logic state.</description>
                  <value>#1</value>
                </enumeratedValue>
              </enumeratedValues>
            </field>
          </fields>
        </register>
        <register>
          <name>PDIR</name>
          <description>Port Data Input Register</description>
          <addressOffset>0x10</addressOffset>
          <size>32</size>
          <access>read-only</access>
          <resetValue>0</resetValue>
          <resetMask>0xFFFFFFFF</resetMask>
          <fields>
            <field>
              <name>PDI</name>
              <description>Port Data Input</description>
              <bitOffset>0</bitOffset>
              <bitWidth>32</bitWidth>
              <access>read-only</access>
              <enumeratedValues>
                <enumeratedValue>
                  <name>0</name>
                  <description>Pin logic level is logic 0, or is not configured for use by digital function.</description>
                  <value>#0</value>
                </enumeratedValue>
                <enumeratedValue>
                  <name>1</name>
                  <description>Pin logic level is logic 1.</description>
                  <value>#1</value>
                </enumeratedValue>
              </enumeratedValues>
            </field>
          </fields>
        </register>
        <register>
          <name>PDDR</name>
          <description>Port Data Direction Register</description>
          <addressOffset>0x14</addressOffset>
          <size>32</size>
          <access>read-write</access>
          <resetValue>0</resetValue>
          <resetMask>0xFFFFFFFF</resetMask>
          <fields>
            <field>
              <name>PDD</name>
              <description>Port Data Direction</description>
              <bitOffset>0</bitOffset>
              <bitWidth>32</bitWidth>
              <access>read-write</access>
              <enumeratedValues>
                <enumeratedValue>
                  <name>0</name>
                  <description>Pin is configured as general-purpose input, for the GPIO function.</description>
                  <value>#0</value>
                </enumeratedValue>
                <enumeratedValue>
                  <name>1</name>
                  <description>Pin is configured as general-purpose output, for the GPIO function.</description>
                  <value>#1</value>
                </enumeratedValue>
              </enumeratedValues>
            </field>
          </fields>
        </register>
      </registers>
    </peripheral>
    <peripheral>
      <name>FGPIOB</name>
      <description>General Purpose Input/Output</description>
      <groupName>FGPIO</groupName>
      <prependToName>FGPIOB_</prependToName>
      <baseAddress>0xF8000040</baseAddress>
      <addressBlock>
        <offset>0</offset>
        <size>0x18</size>
        <usage>registers</usage>
      </addressBlock>
      <registers>
        <register>
          <name>PDOR</name>
          <description>Port Data Output Register</description>
          <addressOffset>0</addressOffset>
          <size>32</size>
          <access>read-write</access>
          <resetValue>0</resetValue>
          <resetMask>0xFFFFFFFF</resetMask>
          <fields>
            <field>
              <name>PDO</name>
              <description>Port Data Output</description>
              <bitOffset>0</bitOffset>
              <bitWidth>32</bitWidth>
              <access>read-write</access>
              <enumeratedValues>
                <enumeratedValue>
                  <name>0</name>
                  <description>Logic level 0 is driven on pin, provided pin is configured for general-purpose output.</description>
                  <value>#0</value>
                </enumeratedValue>
                <enumeratedValue>
                  <name>1</name>
                  <description>Logic level 1 is driven on pin, provided pin is configured for general-purpose output.</description>
                  <value>#1</value>
                </enumeratedValue>
              </enumeratedValues>
            </field>
          </fields>
        </register>
        <register>
          <name>PSOR</name>
          <description>Port Set Output Register</description>
          <addressOffset>0x4</addressOffset>
          <size>32</size>
          <access>write-only</access>
          <resetValue>0</resetValue>
          <resetMask>0xFFFFFFFF</resetMask>
          <fields>
            <field>
              <name>PTSO</name>
              <description>Port Set Output</description>
              <bitOffset>0</bitOffset>
              <bitWidth>32</bitWidth>
              <access>write-only</access>
              <enumeratedValues>
                <enumeratedValue>
                  <name>0</name>
                  <description>Corresponding bit in PDORn does not change.</description>
                  <value>#0</value>
                </enumeratedValue>
                <enumeratedValue>
                  <name>1</name>
                  <description>Corresponding bit in PDORn is set to logic 1.</description>
                  <value>#1</value>
                </enumeratedValue>
              </enumeratedValues>
            </field>
          </fields>
        </register>
        <register>
          <name>PCOR</name>
          <description>Port Clear Output Register</description>
          <addressOffset>0x8</addressOffset>
          <size>32</size>
          <access>write-only</access>
          <resetValue>0</resetValue>
          <resetMask>0xFFFFFFFF</resetMask>
          <fields>
            <field>
              <name>PTCO</name>
              <description>Port Clear Output</description>
              <bitOffset>0</bitOffset>
              <bitWidth>32</bitWidth>
              <access>write-only</access>
              <enumeratedValues>
                <enumeratedValue>
                  <name>0</name>
                  <description>Corresponding bit in PDORn does not change.</description>
                  <value>#0</value>
                </enumeratedValue>
                <enumeratedValue>
                  <name>1</name>
                  <description>Corresponding bit in PDORn is cleared to logic 0.</description>
                  <value>#1</value>
                </enumeratedValue>
              </enumeratedValues>
            </field>
          </fields>
        </register>
        <register>
          <name>PTOR</name>
          <description>Port Toggle Output Register</description>
          <addressOffset>0xC</addressOffset>
          <size>32</size>
          <access>write-only</access>
          <resetValue>0</resetValue>
          <resetMask>0xFFFFFFFF</resetMask>
          <fields>
            <field>
              <name>PTTO</name>
              <description>Port Toggle Output</description>
              <bitOffset>0</bitOffset>
              <bitWidth>32</bitWidth>
              <access>write-only</access>
              <enumeratedValues>
                <enumeratedValue>
                  <name>0</name>
                  <description>Corresponding bit in PDORn does not change.</description>
                  <value>#0</value>
                </enumeratedValue>
                <enumeratedValue>
                  <name>1</name>
                  <description>Corresponding bit in PDORn is set to the inverse of its existing logic state.</description>
                  <value>#1</value>
                </enumeratedValue>
              </enumeratedValues>
            </field>
          </fields>
        </register>
        <register>
          <name>PDIR</name>
          <description>Port Data Input Register</description>
          <addressOffset>0x10</addressOffset>
          <size>32</size>
          <access>read-only</access>
          <resetValue>0</resetValue>
          <resetMask>0xFFFFFFFF</resetMask>
          <fields>
            <field>
              <name>PDI</name>
              <description>Port Data Input</description>
              <bitOffset>0</bitOffset>
              <bitWidth>32</bitWidth>
              <access>read-only</access>
              <enumeratedValues>
                <enumeratedValue>
                  <name>0</name>
                  <description>Pin logic level is logic 0, or is not configured for use by digital function.</description>
                  <value>#0</value>
                </enumeratedValue>
                <enumeratedValue>
                  <name>1</name>
                  <description>Pin logic level is logic 1.</description>
                  <value>#1</value>
                </enumeratedValue>
              </enumeratedValues>
            </field>
          </fields>
        </register>
        <register>
          <name>PDDR</name>
          <description>Port Data Direction Register</description>
          <addressOffset>0x14</addressOffset>
          <size>32</size>
          <access>read-write</access>
          <resetValue>0</resetValue>
          <resetMask>0xFFFFFFFF</resetMask>
          <fields>
            <field>
              <name>PDD</name>
              <description>Port Data Direction</description>
              <bitOffset>0</bitOffset>
              <bitWidth>32</bitWidth>
              <access>read-write</access>
              <enumeratedValues>
                <enumeratedValue>
                  <name>0</name>
                  <description>Pin is configured as general-purpose input, for the GPIO function.</description>
                  <value>#0</value>
                </enumeratedValue>
                <enumeratedValue>
                  <name>1</name>
                  <description>Pin is configured as general-purpose output, for the GPIO function.</description>
                  <value>#1</value>
                </enumeratedValue>
              </enumeratedValues>
            </field>
          </fields>
        </register>
      </registers>
    </peripheral>
    <peripheral>
      <name>FGPIOC</name>
      <description>General Purpose Input/Output</description>
      <groupName>FGPIO</groupName>
      <prependToName>FGPIOC_</prependToName>
      <baseAddress>0xF8000080</baseAddress>
      <addressBlock>
        <offset>0</offset>
        <size>0x18</size>
        <usage>registers</usage>
      </addressBlock>
      <registers>
        <register>
          <name>PDOR</name>
          <description>Port Data Output Register</description>
          <addressOffset>0</addressOffset>
          <size>32</size>
          <access>read-write</access>
          <resetValue>0</resetValue>
          <resetMask>0xFFFFFFFF</resetMask>
          <fields>
            <field>
              <name>PDO</name>
              <description>Port Data Output</description>
              <bitOffset>0</bitOffset>
              <bitWidth>32</bitWidth>
              <access>read-write</access>
              <enumeratedValues>
                <enumeratedValue>
                  <name>0</name>
                  <description>Logic level 0 is driven on pin, provided pin is configured for general-purpose output.</description>
                  <value>#0</value>
                </enumeratedValue>
                <enumeratedValue>
                  <name>1</name>
                  <description>Logic level 1 is driven on pin, provided pin is configured for general-purpose output.</description>
                  <value>#1</value>
                </enumeratedValue>
              </enumeratedValues>
            </field>
          </fields>
        </register>
        <register>
          <name>PSOR</name>
          <description>Port Set Output Register</description>
          <addressOffset>0x4</addressOffset>
          <size>32</size>
          <access>write-only</access>
          <resetValue>0</resetValue>
          <resetMask>0xFFFFFFFF</resetMask>
          <fields>
            <field>
              <name>PTSO</name>
              <description>Port Set Output</description>
              <bitOffset>0</bitOffset>
              <bitWidth>32</bitWidth>
              <access>write-only</access>
              <enumeratedValues>
                <enumeratedValue>
                  <name>0</name>
                  <description>Corresponding bit in PDORn does not change.</description>
                  <value>#0</value>
                </enumeratedValue>
                <enumeratedValue>
                  <name>1</name>
                  <description>Corresponding bit in PDORn is set to logic 1.</description>
                  <value>#1</value>
                </enumeratedValue>
              </enumeratedValues>
            </field>
          </fields>
        </register>
        <register>
          <name>PCOR</name>
          <description>Port Clear Output Register</description>
          <addressOffset>0x8</addressOffset>
          <size>32</size>
          <access>write-only</access>
          <resetValue>0</resetValue>
          <resetMask>0xFFFFFFFF</resetMask>
          <fields>
            <field>
              <name>PTCO</name>
              <description>Port Clear Output</description>
              <bitOffset>0</bitOffset>
              <bitWidth>32</bitWidth>
              <access>write-only</access>
              <enumeratedValues>
                <enumeratedValue>
                  <name>0</name>
                  <description>Corresponding bit in PDORn does not change.</description>
                  <value>#0</value>
                </enumeratedValue>
                <enumeratedValue>
                  <name>1</name>
                  <description>Corresponding bit in PDORn is cleared to logic 0.</description>
                  <value>#1</value>
                </enumeratedValue>
              </enumeratedValues>
            </field>
          </fields>
        </register>
        <register>
          <name>PTOR</name>
          <description>Port Toggle Output Register</description>
          <addressOffset>0xC</addressOffset>
          <size>32</size>
          <access>write-only</access>
          <resetValue>0</resetValue>
          <resetMask>0xFFFFFFFF</resetMask>
          <fields>
            <field>
              <name>PTTO</name>
              <description>Port Toggle Output</description>
              <bitOffset>0</bitOffset>
              <bitWidth>32</bitWidth>
              <access>write-only</access>
              <enumeratedValues>
                <enumeratedValue>
                  <name>0</name>
                  <description>Corresponding bit in PDORn does not change.</description>
                  <value>#0</value>
                </enumeratedValue>
                <enumeratedValue>
                  <name>1</name>
                  <description>Corresponding bit in PDORn is set to the inverse of its existing logic state.</description>
                  <value>#1</value>
                </enumeratedValue>
              </enumeratedValues>
            </field>
          </fields>
        </register>
        <register>
          <name>PDIR</name>
          <description>Port Data Input Register</description>
          <addressOffset>0x10</addressOffset>
          <size>32</size>
          <access>read-only</access>
          <resetValue>0</resetValue>
          <resetMask>0xFFFFFFFF</resetMask>
          <fields>
            <field>
              <name>PDI</name>
              <description>Port Data Input</description>
              <bitOffset>0</bitOffset>
              <bitWidth>32</bitWidth>
              <access>read-only</access>
              <enumeratedValues>
                <enumeratedValue>
                  <name>0</name>
                  <description>Pin logic level is logic 0, or is not configured for use by digital function.</description>
                  <value>#0</value>
                </enumeratedValue>
                <enumeratedValue>
                  <name>1</name>
                  <description>Pin logic level is logic 1.</description>
                  <value>#1</value>
                </enumeratedValue>
              </enumeratedValues>
            </field>
          </fields>
        </register>
        <register>
          <name>PDDR</name>
          <description>Port Data Direction Register</description>
          <addressOffset>0x14</addressOffset>
          <size>32</size>
          <access>read-write</access>
          <resetValue>0</resetValue>
          <resetMask>0xFFFFFFFF</resetMask>
          <fields>
            <field>
              <name>PDD</name>
              <description>Port Data Direction</description>
              <bitOffset>0</bitOffset>
              <bitWidth>32</bitWidth>
              <access>read-write</access>
              <enumeratedValues>
                <enumeratedValue>
                  <name>0</name>
                  <description>Pin is configured as general-purpose input, for the GPIO function.</description>
                  <value>#0</value>
                </enumeratedValue>
                <enumeratedValue>
                  <name>1</name>
                  <description>Pin is configured as general-purpose output, for the GPIO function.</description>
                  <value>#1</value>
                </enumeratedValue>
              </enumeratedValues>
            </field>
          </fields>
        </register>
      </registers>
    </peripheral>
    <peripheral>
      <name>FGPIOD</name>
      <description>General Purpose Input/Output</description>
      <groupName>FGPIO</groupName>
      <prependToName>FGPIOD_</prependToName>
      <baseAddress>0xF80000C0</baseAddress>
      <addressBlock>
        <offset>0</offset>
        <size>0x18</size>
        <usage>registers</usage>
      </addressBlock>
      <registers>
        <register>
          <name>PDOR</name>
          <description>Port Data Output Register</description>
          <addressOffset>0</addressOffset>
          <size>32</size>
          <access>read-write</access>
          <resetValue>0</resetValue>
          <resetMask>0xFFFFFFFF</resetMask>
          <fields>
            <field>
              <name>PDO</name>
              <description>Port Data Output</description>
              <bitOffset>0</bitOffset>
              <bitWidth>32</bitWidth>
              <access>read-write</access>
              <enumeratedValues>
                <enumeratedValue>
                  <name>0</name>
                  <description>Logic level 0 is driven on pin, provided pin is configured for general-purpose output.</description>
                  <value>#0</value>
                </enumeratedValue>
                <enumeratedValue>
                  <name>1</name>
                  <description>Logic level 1 is driven on pin, provided pin is configured for general-purpose output.</description>
                  <value>#1</value>
                </enumeratedValue>
              </enumeratedValues>
            </field>
          </fields>
        </register>
        <register>
          <name>PSOR</name>
          <description>Port Set Output Register</description>
          <addressOffset>0x4</addressOffset>
          <size>32</size>
          <access>write-only</access>
          <resetValue>0</resetValue>
          <resetMask>0xFFFFFFFF</resetMask>
          <fields>
            <field>
              <name>PTSO</name>
              <description>Port Set Output</description>
              <bitOffset>0</bitOffset>
              <bitWidth>32</bitWidth>
              <access>write-only</access>
              <enumeratedValues>
                <enumeratedValue>
                  <name>0</name>
                  <description>Corresponding bit in PDORn does not change.</description>
                  <value>#0</value>
                </enumeratedValue>
                <enumeratedValue>
                  <name>1</name>
                  <description>Corresponding bit in PDORn is set to logic 1.</description>
                  <value>#1</value>
                </enumeratedValue>
              </enumeratedValues>
            </field>
          </fields>
        </register>
        <register>
          <name>PCOR</name>
          <description>Port Clear Output Register</description>
          <addressOffset>0x8</addressOffset>
          <size>32</size>
          <access>write-only</access>
          <resetValue>0</resetValue>
          <resetMask>0xFFFFFFFF</resetMask>
          <fields>
            <field>
              <name>PTCO</name>
              <description>Port Clear Output</description>
              <bitOffset>0</bitOffset>
              <bitWidth>32</bitWidth>
              <access>write-only</access>
              <enumeratedValues>
                <enumeratedValue>
                  <name>0</name>
                  <description>Corresponding bit in PDORn does not change.</description>
                  <value>#0</value>
                </enumeratedValue>
                <enumeratedValue>
                  <name>1</name>
                  <description>Corresponding bit in PDORn is cleared to logic 0.</description>
                  <value>#1</value>
                </enumeratedValue>
              </enumeratedValues>
            </field>
          </fields>
        </register>
        <register>
          <name>PTOR</name>
          <description>Port Toggle Output Register</description>
          <addressOffset>0xC</addressOffset>
          <size>32</size>
          <access>write-only</access>
          <resetValue>0</resetValue>
          <resetMask>0xFFFFFFFF</resetMask>
          <fields>
            <field>
              <name>PTTO</name>
              <description>Port Toggle Output</description>
              <bitOffset>0</bitOffset>
              <bitWidth>32</bitWidth>
              <access>write-only</access>
              <enumeratedValues>
                <enumeratedValue>
                  <name>0</name>
                  <description>Corresponding bit in PDORn does not change.</description>
                  <value>#0</value>
                </enumeratedValue>
                <enumeratedValue>
                  <name>1</name>
                  <description>Corresponding bit in PDORn is set to the inverse of its existing logic state.</description>
                  <value>#1</value>
                </enumeratedValue>
              </enumeratedValues>
            </field>
          </fields>
        </register>
        <register>
          <name>PDIR</name>
          <description>Port Data Input Register</description>
          <addressOffset>0x10</addressOffset>
          <size>32</size>
          <access>read-only</access>
          <resetValue>0</resetValue>
          <resetMask>0xFFFFFFFF</resetMask>
          <fields>
            <field>
              <name>PDI</name>
              <description>Port Data Input</description>
              <bitOffset>0</bitOffset>
              <bitWidth>32</bitWidth>
              <access>read-only</access>
              <enumeratedValues>
                <enumeratedValue>
                  <name>0</name>
                  <description>Pin logic level is logic 0, or is not configured for use by digital function.</description>
                  <value>#0</value>
                </enumeratedValue>
                <enumeratedValue>
                  <name>1</name>
                  <description>Pin logic level is logic 1.</description>
                  <value>#1</value>
                </enumeratedValue>
              </enumeratedValues>
            </field>
          </fields>
        </register>
        <register>
          <name>PDDR</name>
          <description>Port Data Direction Register</description>
          <addressOffset>0x14</addressOffset>
          <size>32</size>
          <access>read-write</access>
          <resetValue>0</resetValue>
          <resetMask>0xFFFFFFFF</resetMask>
          <fields>
            <field>
              <name>PDD</name>
              <description>Port Data Direction</description>
              <bitOffset>0</bitOffset>
              <bitWidth>32</bitWidth>
              <access>read-write</access>
              <enumeratedValues>
                <enumeratedValue>
                  <name>0</name>
                  <description>Pin is configured as general-purpose input, for the GPIO function.</description>
                  <value>#0</value>
                </enumeratedValue>
                <enumeratedValue>
                  <name>1</name>
                  <description>Pin is configured as general-purpose output, for the GPIO function.</description>
                  <value>#1</value>
                </enumeratedValue>
              </enumeratedValues>
            </field>
          </fields>
        </register>
      </registers>
    </peripheral>
    <peripheral>
      <name>FGPIOE</name>
      <description>General Purpose Input/Output</description>
      <groupName>FGPIO</groupName>
      <prependToName>FGPIOE_</prependToName>
      <baseAddress>0xF8000100</baseAddress>
      <addressBlock>
        <offset>0</offset>
        <size>0x18</size>
        <usage>registers</usage>
      </addressBlock>
      <registers>
        <register>
          <name>PDOR</name>
          <description>Port Data Output Register</description>
          <addressOffset>0</addressOffset>
          <size>32</size>
          <access>read-write</access>
          <resetValue>0</resetValue>
          <resetMask>0xFFFFFFFF</resetMask>
          <fields>
            <field>
              <name>PDO</name>
              <description>Port Data Output</description>
              <bitOffset>0</bitOffset>
              <bitWidth>32</bitWidth>
              <access>read-write</access>
              <enumeratedValues>
                <enumeratedValue>
                  <name>0</name>
                  <description>Logic level 0 is driven on pin, provided pin is configured for general-purpose output.</description>
                  <value>#0</value>
                </enumeratedValue>
                <enumeratedValue>
                  <name>1</name>
                  <description>Logic level 1 is driven on pin, provided pin is configured for general-purpose output.</description>
                  <value>#1</value>
                </enumeratedValue>
              </enumeratedValues>
            </field>
          </fields>
        </register>
        <register>
          <name>PSOR</name>
          <description>Port Set Output Register</description>
          <addressOffset>0x4</addressOffset>
          <size>32</size>
          <access>write-only</access>
          <resetValue>0</resetValue>
          <resetMask>0xFFFFFFFF</resetMask>
          <fields>
            <field>
              <name>PTSO</name>
              <description>Port Set Output</description>
              <bitOffset>0</bitOffset>
              <bitWidth>32</bitWidth>
              <access>write-only</access>
              <enumeratedValues>
                <enumeratedValue>
                  <name>0</name>
                  <description>Corresponding bit in PDORn does not change.</description>
                  <value>#0</value>
                </enumeratedValue>
                <enumeratedValue>
                  <name>1</name>
                  <description>Corresponding bit in PDORn is set to logic 1.</description>
                  <value>#1</value>
                </enumeratedValue>
              </enumeratedValues>
            </field>
          </fields>
        </register>
        <register>
          <name>PCOR</name>
          <description>Port Clear Output Register</description>
          <addressOffset>0x8</addressOffset>
          <size>32</size>
          <access>write-only</access>
          <resetValue>0</resetValue>
          <resetMask>0xFFFFFFFF</resetMask>
          <fields>
            <field>
              <name>PTCO</name>
              <description>Port Clear Output</description>
              <bitOffset>0</bitOffset>
              <bitWidth>32</bitWidth>
              <access>write-only</access>
              <enumeratedValues>
                <enumeratedValue>
                  <name>0</name>
                  <description>Corresponding bit in PDORn does not change.</description>
                  <value>#0</value>
                </enumeratedValue>
                <enumeratedValue>
                  <name>1</name>
                  <description>Corresponding bit in PDORn is cleared to logic 0.</description>
                  <value>#1</value>
                </enumeratedValue>
              </enumeratedValues>
            </field>
          </fields>
        </register>
        <register>
          <name>PTOR</name>
          <description>Port Toggle Output Register</description>
          <addressOffset>0xC</addressOffset>
          <size>32</size>
          <access>write-only</access>
          <resetValue>0</resetValue>
          <resetMask>0xFFFFFFFF</resetMask>
          <fields>
            <field>
              <name>PTTO</name>
              <description>Port Toggle Output</description>
              <bitOffset>0</bitOffset>
              <bitWidth>32</bitWidth>
              <access>write-only</access>
              <enumeratedValues>
                <enumeratedValue>
                  <name>0</name>
                  <description>Corresponding bit in PDORn does not change.</description>
                  <value>#0</value>
                </enumeratedValue>
                <enumeratedValue>
                  <name>1</name>
                  <description>Corresponding bit in PDORn is set to the inverse of its existing logic state.</description>
                  <value>#1</value>
                </enumeratedValue>
              </enumeratedValues>
            </field>
          </fields>
        </register>
        <register>
          <name>PDIR</name>
          <description>Port Data Input Register</description>
          <addressOffset>0x10</addressOffset>
          <size>32</size>
          <access>read-only</access>
          <resetValue>0</resetValue>
          <resetMask>0xFFFFFFFF</resetMask>
          <fields>
            <field>
              <name>PDI</name>
              <description>Port Data Input</description>
              <bitOffset>0</bitOffset>
              <bitWidth>32</bitWidth>
              <access>read-only</access>
              <enumeratedValues>
                <enumeratedValue>
                  <name>0</name>
                  <description>Pin logic level is logic 0, or is not configured for use by digital function.</description>
                  <value>#0</value>
                </enumeratedValue>
                <enumeratedValue>
                  <name>1</name>
                  <description>Pin logic level is logic 1.</description>
                  <value>#1</value>
                </enumeratedValue>
              </enumeratedValues>
            </field>
          </fields>
        </register>
        <register>
          <name>PDDR</name>
          <description>Port Data Direction Register</description>
          <addressOffset>0x14</addressOffset>
          <size>32</size>
          <access>read-write</access>
          <resetValue>0</resetValue>
          <resetMask>0xFFFFFFFF</resetMask>
          <fields>
            <field>
              <name>PDD</name>
              <description>Port Data Direction</description>
              <bitOffset>0</bitOffset>
              <bitWidth>32</bitWidth>
              <access>read-write</access>
              <enumeratedValues>
                <enumeratedValue>
                  <name>0</name>
                  <description>Pin is configured as general-purpose input, for the GPIO function.</description>
                  <value>#0</value>
                </enumeratedValue>
                <enumeratedValue>
                  <name>1</name>
                  <description>Pin is configured as general-purpose output, for the GPIO function.</description>
                  <value>#1</value>
                </enumeratedValue>
              </enumeratedValues>
            </field>
          </fields>
        </register>
      </registers>
    </peripheral>
  </peripherals>
</device>
